VERSION 5.8 ;
BUSBITCHARS "[]" ;
DIVIDERCHAR "/" ;
UNITS
    DATABASE MICRONS 1000 ;
END UNITS

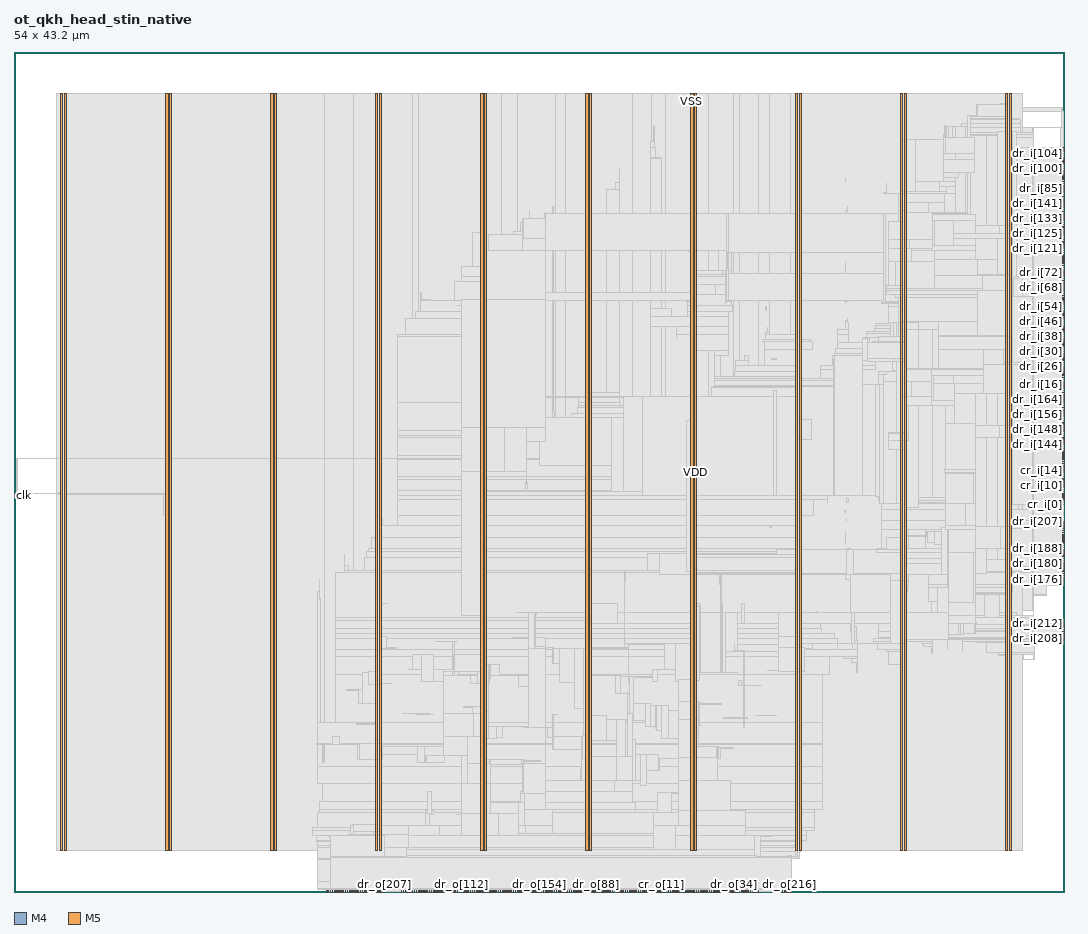
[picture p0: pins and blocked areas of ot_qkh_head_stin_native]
MACRO ot_qkh_head_stin_native
  FOREIGN ot_qkh_head_stin_native 0 0 ;
  CLASS BLOCK ;
  SIZE 54 BY 43.2 ;
  PIN clk
    DIRECTION INPUT ;
    USE SIGNAL ;
    PORT
      LAYER M4 ;
        RECT  0 20.4 0.084 20.424 ;
    END
  END clk
  PIN cr_i[0]
    DIRECTION INPUT ;
    USE SIGNAL ;
    PORT
      LAYER M4 ;
        RECT  53.916 19.92 54 19.944 ;
    END
  END cr_i[0]
  PIN cr_i[10]
    DIRECTION INPUT ;
    USE SIGNAL ;
    PORT
      LAYER M4 ;
        RECT  53.916 20.88 54 20.904 ;
    END
  END cr_i[10]
  PIN cr_i[11]
    DIRECTION INPUT ;
    USE SIGNAL ;
    PORT
      LAYER M4 ;
        RECT  53.916 20.976 54 21 ;
    END
  END cr_i[11]
  PIN cr_i[12]
    DIRECTION INPUT ;
    USE SIGNAL ;
    PORT
      LAYER M4 ;
        RECT  53.916 21.072 54 21.096 ;
    END
  END cr_i[12]
  PIN cr_i[13]
    DIRECTION INPUT ;
    USE SIGNAL ;
    PORT
      LAYER M4 ;
        RECT  53.916 21.168 54 21.192 ;
    END
  END cr_i[13]
  PIN cr_i[14]
    DIRECTION INPUT ;
    USE SIGNAL ;
    PORT
      LAYER M4 ;
        RECT  53.916 21.264 54 21.288 ;
    END
  END cr_i[14]
  PIN cr_i[15]
    DIRECTION INPUT ;
    USE SIGNAL ;
    PORT
      LAYER M4 ;
        RECT  53.916 21.36 54 21.384 ;
    END
  END cr_i[15]
  PIN cr_i[1]
    DIRECTION INPUT ;
    USE SIGNAL ;
    PORT
      LAYER M4 ;
        RECT  53.916 20.016 54 20.04 ;
    END
  END cr_i[1]
  PIN cr_i[2]
    DIRECTION INPUT ;
    USE SIGNAL ;
    PORT
      LAYER M4 ;
        RECT  53.916 20.112 54 20.136 ;
    END
  END cr_i[2]
  PIN cr_i[3]
    DIRECTION INPUT ;
    USE SIGNAL ;
    PORT
      LAYER M4 ;
        RECT  53.916 20.208 54 20.232 ;
    END
  END cr_i[3]
  PIN cr_i[4]
    DIRECTION INPUT ;
    USE SIGNAL ;
    PORT
      LAYER M4 ;
        RECT  53.916 20.304 54 20.328 ;
    END
  END cr_i[4]
  PIN cr_i[5]
    DIRECTION INPUT ;
    USE SIGNAL ;
    PORT
      LAYER M4 ;
        RECT  53.916 20.4 54 20.424 ;
    END
  END cr_i[5]
  PIN cr_i[6]
    DIRECTION INPUT ;
    USE SIGNAL ;
    PORT
      LAYER M4 ;
        RECT  53.916 20.496 54 20.52 ;
    END
  END cr_i[6]
  PIN cr_i[7]
    DIRECTION INPUT ;
    USE SIGNAL ;
    PORT
      LAYER M4 ;
        RECT  53.916 20.592 54 20.616 ;
    END
  END cr_i[7]
  PIN cr_i[8]
    DIRECTION INPUT ;
    USE SIGNAL ;
    PORT
      LAYER M4 ;
        RECT  53.916 20.688 54 20.712 ;
    END
  END cr_i[8]
  PIN cr_i[9]
    DIRECTION INPUT ;
    USE SIGNAL ;
    PORT
      LAYER M4 ;
        RECT  53.916 20.784 54 20.808 ;
    END
  END cr_i[9]
  PIN cr_o[0]
    DIRECTION OUTPUT ;
    USE SIGNAL ;
    PORT
      LAYER M5 ;
        RECT  32.208 0 32.232 0.084 ;
    END
  END cr_o[0]
  PIN cr_o[10]
    DIRECTION OUTPUT ;
    USE SIGNAL ;
    PORT
      LAYER M5 ;
        RECT  33.168 0 33.192 0.084 ;
    END
  END cr_o[10]
  PIN cr_o[11]
    DIRECTION OUTPUT ;
    USE SIGNAL ;
    PORT
      LAYER M5 ;
        RECT  33.264 0 33.288 0.084 ;
    END
  END cr_o[11]
  PIN cr_o[12]
    DIRECTION OUTPUT ;
    USE SIGNAL ;
    PORT
      LAYER M5 ;
        RECT  33.36 0 33.384 0.084 ;
    END
  END cr_o[12]
  PIN cr_o[13]
    DIRECTION OUTPUT ;
    USE SIGNAL ;
    PORT
      LAYER M5 ;
        RECT  33.456 0 33.48 0.084 ;
    END
  END cr_o[13]
  PIN cr_o[14]
    DIRECTION OUTPUT ;
    USE SIGNAL ;
    PORT
      LAYER M5 ;
        RECT  33.552 0 33.576 0.084 ;
    END
  END cr_o[14]
  PIN cr_o[15]
    DIRECTION OUTPUT ;
    USE SIGNAL ;
    PORT
      LAYER M5 ;
        RECT  33.648 0 33.672 0.084 ;
    END
  END cr_o[15]
  PIN cr_o[1]
    DIRECTION OUTPUT ;
    USE SIGNAL ;
    PORT
      LAYER M5 ;
        RECT  32.304 0 32.328 0.084 ;
    END
  END cr_o[1]
  PIN cr_o[2]
    DIRECTION OUTPUT ;
    USE SIGNAL ;
    PORT
      LAYER M5 ;
        RECT  32.4 0 32.424 0.084 ;
    END
  END cr_o[2]
  PIN cr_o[3]
    DIRECTION OUTPUT ;
    USE SIGNAL ;
    PORT
      LAYER M5 ;
        RECT  32.496 0 32.52 0.084 ;
    END
  END cr_o[3]
  PIN cr_o[4]
    DIRECTION OUTPUT ;
    USE SIGNAL ;
    PORT
      LAYER M5 ;
        RECT  32.592 0 32.616 0.084 ;
    END
  END cr_o[4]
  PIN cr_o[5]
    DIRECTION OUTPUT ;
    USE SIGNAL ;
    PORT
      LAYER M5 ;
        RECT  32.688 0 32.712 0.084 ;
    END
  END cr_o[5]
  PIN cr_o[6]
    DIRECTION OUTPUT ;
    USE SIGNAL ;
    PORT
      LAYER M5 ;
        RECT  32.784 0 32.808 0.084 ;
    END
  END cr_o[6]
  PIN cr_o[7]
    DIRECTION OUTPUT ;
    USE SIGNAL ;
    PORT
      LAYER M5 ;
        RECT  32.88 0 32.904 0.084 ;
    END
  END cr_o[7]
  PIN cr_o[8]
    DIRECTION OUTPUT ;
    USE SIGNAL ;
    PORT
      LAYER M5 ;
        RECT  32.976 0 33 0.084 ;
    END
  END cr_o[8]
  PIN cr_o[9]
    DIRECTION OUTPUT ;
    USE SIGNAL ;
    PORT
      LAYER M5 ;
        RECT  33.072 0 33.096 0.084 ;
    END
  END cr_o[9]
  PIN dr_i[0]
    DIRECTION INPUT ;
    USE SIGNAL ;
    PORT
      LAYER M4 ;
        RECT  53.916 21.456 54 21.48 ;
    END
  END dr_i[0]
  PIN dr_i[100]
    DIRECTION INPUT ;
    USE SIGNAL ;
    PORT
      LAYER M4 ;
        RECT  53.916 37.2 54 37.224 ;
    END
  END dr_i[100]
  PIN dr_i[101]
    DIRECTION INPUT ;
    USE SIGNAL ;
    PORT
      LAYER M4 ;
        RECT  53.916 37.296 54 37.32 ;
    END
  END dr_i[101]
  PIN dr_i[102]
    DIRECTION INPUT ;
    USE SIGNAL ;
    PORT
      LAYER M4 ;
        RECT  53.916 37.392 54 37.416 ;
    END
  END dr_i[102]
  PIN dr_i[103]
    DIRECTION INPUT ;
    USE SIGNAL ;
    PORT
      LAYER M4 ;
        RECT  53.916 37.488 54 37.512 ;
    END
  END dr_i[103]
  PIN dr_i[104]
    DIRECTION INPUT ;
    USE SIGNAL ;
    PORT
      LAYER M4 ;
        RECT  53.916 37.584 54 37.608 ;
    END
  END dr_i[104]
  PIN dr_i[105]
    DIRECTION INPUT ;
    USE SIGNAL ;
    PORT
      LAYER M4 ;
        RECT  53.916 37.68 54 37.704 ;
    END
  END dr_i[105]
  PIN dr_i[106]
    DIRECTION INPUT ;
    USE SIGNAL ;
    PORT
      LAYER M4 ;
        RECT  53.916 37.776 54 37.8 ;
    END
  END dr_i[106]
  PIN dr_i[107]
    DIRECTION INPUT ;
    USE SIGNAL ;
    PORT
      LAYER M4 ;
        RECT  53.916 37.872 54 37.896 ;
    END
  END dr_i[107]
  PIN dr_i[108]
    DIRECTION INPUT ;
    USE SIGNAL ;
    PORT
      LAYER M4 ;
        RECT  53.916 37.968 54 37.992 ;
    END
  END dr_i[108]
  PIN dr_i[109]
    DIRECTION INPUT ;
    USE SIGNAL ;
    PORT
      LAYER M4 ;
        RECT  53.916 38.064 54 38.088 ;
    END
  END dr_i[109]
  PIN dr_i[10]
    DIRECTION INPUT ;
    USE SIGNAL ;
    PORT
      LAYER M4 ;
        RECT  53.916 22.416 54 22.44 ;
    END
  END dr_i[10]
  PIN dr_i[110]
    DIRECTION INPUT ;
    USE SIGNAL ;
    PORT
      LAYER M4 ;
        RECT  53.916 38.16 54 38.184 ;
    END
  END dr_i[110]
  PIN dr_i[111]
    DIRECTION INPUT ;
    USE SIGNAL ;
    PORT
      LAYER M4 ;
        RECT  53.916 38.256 54 38.28 ;
    END
  END dr_i[111]
  PIN dr_i[112]
    DIRECTION INPUT ;
    USE SIGNAL ;
    PORT
      LAYER M4 ;
        RECT  53.916 32.208 54 32.232 ;
    END
  END dr_i[112]
  PIN dr_i[113]
    DIRECTION INPUT ;
    USE SIGNAL ;
    PORT
      LAYER M4 ;
        RECT  53.916 32.304 54 32.328 ;
    END
  END dr_i[113]
  PIN dr_i[114]
    DIRECTION INPUT ;
    USE SIGNAL ;
    PORT
      LAYER M4 ;
        RECT  53.916 32.4 54 32.424 ;
    END
  END dr_i[114]
  PIN dr_i[115]
    DIRECTION INPUT ;
    USE SIGNAL ;
    PORT
      LAYER M4 ;
        RECT  53.916 32.496 54 32.52 ;
    END
  END dr_i[115]
  PIN dr_i[116]
    DIRECTION INPUT ;
    USE SIGNAL ;
    PORT
      LAYER M4 ;
        RECT  53.916 32.592 54 32.616 ;
    END
  END dr_i[116]
  PIN dr_i[117]
    DIRECTION INPUT ;
    USE SIGNAL ;
    PORT
      LAYER M4 ;
        RECT  53.916 32.688 54 32.712 ;
    END
  END dr_i[117]
  PIN dr_i[118]
    DIRECTION INPUT ;
    USE SIGNAL ;
    PORT
      LAYER M4 ;
        RECT  53.916 32.784 54 32.808 ;
    END
  END dr_i[118]
  PIN dr_i[119]
    DIRECTION INPUT ;
    USE SIGNAL ;
    PORT
      LAYER M4 ;
        RECT  53.916 32.88 54 32.904 ;
    END
  END dr_i[119]
  PIN dr_i[11]
    DIRECTION INPUT ;
    USE SIGNAL ;
    PORT
      LAYER M4 ;
        RECT  53.916 22.512 54 22.536 ;
    END
  END dr_i[11]
  PIN dr_i[120]
    DIRECTION INPUT ;
    USE SIGNAL ;
    PORT
      LAYER M4 ;
        RECT  53.916 32.976 54 33 ;
    END
  END dr_i[120]
  PIN dr_i[121]
    DIRECTION INPUT ;
    USE SIGNAL ;
    PORT
      LAYER M4 ;
        RECT  53.916 33.072 54 33.096 ;
    END
  END dr_i[121]
  PIN dr_i[122]
    DIRECTION INPUT ;
    USE SIGNAL ;
    PORT
      LAYER M4 ;
        RECT  53.916 33.168 54 33.192 ;
    END
  END dr_i[122]
  PIN dr_i[123]
    DIRECTION INPUT ;
    USE SIGNAL ;
    PORT
      LAYER M4 ;
        RECT  53.916 33.264 54 33.288 ;
    END
  END dr_i[123]
  PIN dr_i[124]
    DIRECTION INPUT ;
    USE SIGNAL ;
    PORT
      LAYER M4 ;
        RECT  53.916 33.36 54 33.384 ;
    END
  END dr_i[124]
  PIN dr_i[125]
    DIRECTION INPUT ;
    USE SIGNAL ;
    PORT
      LAYER M4 ;
        RECT  53.916 33.456 54 33.48 ;
    END
  END dr_i[125]
  PIN dr_i[126]
    DIRECTION INPUT ;
    USE SIGNAL ;
    PORT
      LAYER M4 ;
        RECT  53.916 33.552 54 33.576 ;
    END
  END dr_i[126]
  PIN dr_i[127]
    DIRECTION INPUT ;
    USE SIGNAL ;
    PORT
      LAYER M4 ;
        RECT  53.916 33.648 54 33.672 ;
    END
  END dr_i[127]
  PIN dr_i[128]
    DIRECTION INPUT ;
    USE SIGNAL ;
    PORT
      LAYER M4 ;
        RECT  53.916 33.744 54 33.768 ;
    END
  END dr_i[128]
  PIN dr_i[129]
    DIRECTION INPUT ;
    USE SIGNAL ;
    PORT
      LAYER M4 ;
        RECT  53.916 33.84 54 33.864 ;
    END
  END dr_i[129]
  PIN dr_i[12]
    DIRECTION INPUT ;
    USE SIGNAL ;
    PORT
      LAYER M4 ;
        RECT  53.916 22.608 54 22.632 ;
    END
  END dr_i[12]
  PIN dr_i[130]
    DIRECTION INPUT ;
    USE SIGNAL ;
    PORT
      LAYER M4 ;
        RECT  53.916 33.936 54 33.96 ;
    END
  END dr_i[130]
  PIN dr_i[131]
    DIRECTION INPUT ;
    USE SIGNAL ;
    PORT
      LAYER M4 ;
        RECT  53.916 34.032 54 34.056 ;
    END
  END dr_i[131]
  PIN dr_i[132]
    DIRECTION INPUT ;
    USE SIGNAL ;
    PORT
      LAYER M4 ;
        RECT  53.916 34.128 54 34.152 ;
    END
  END dr_i[132]
  PIN dr_i[133]
    DIRECTION INPUT ;
    USE SIGNAL ;
    PORT
      LAYER M4 ;
        RECT  53.916 34.224 54 34.248 ;
    END
  END dr_i[133]
  PIN dr_i[134]
    DIRECTION INPUT ;
    USE SIGNAL ;
    PORT
      LAYER M4 ;
        RECT  53.916 34.32 54 34.344 ;
    END
  END dr_i[134]
  PIN dr_i[135]
    DIRECTION INPUT ;
    USE SIGNAL ;
    PORT
      LAYER M4 ;
        RECT  53.916 34.416 54 34.44 ;
    END
  END dr_i[135]
  PIN dr_i[136]
    DIRECTION INPUT ;
    USE SIGNAL ;
    PORT
      LAYER M4 ;
        RECT  53.916 34.512 54 34.536 ;
    END
  END dr_i[136]
  PIN dr_i[137]
    DIRECTION INPUT ;
    USE SIGNAL ;
    PORT
      LAYER M4 ;
        RECT  53.916 34.608 54 34.632 ;
    END
  END dr_i[137]
  PIN dr_i[138]
    DIRECTION INPUT ;
    USE SIGNAL ;
    PORT
      LAYER M4 ;
        RECT  53.916 34.704 54 34.728 ;
    END
  END dr_i[138]
  PIN dr_i[139]
    DIRECTION INPUT ;
    USE SIGNAL ;
    PORT
      LAYER M4 ;
        RECT  53.916 34.8 54 34.824 ;
    END
  END dr_i[139]
  PIN dr_i[13]
    DIRECTION INPUT ;
    USE SIGNAL ;
    PORT
      LAYER M4 ;
        RECT  53.916 22.704 54 22.728 ;
    END
  END dr_i[13]
  PIN dr_i[140]
    DIRECTION INPUT ;
    USE SIGNAL ;
    PORT
      LAYER M4 ;
        RECT  53.916 34.896 54 34.92 ;
    END
  END dr_i[140]
  PIN dr_i[141]
    DIRECTION INPUT ;
    USE SIGNAL ;
    PORT
      LAYER M4 ;
        RECT  53.916 34.992 54 35.016 ;
    END
  END dr_i[141]
  PIN dr_i[142]
    DIRECTION INPUT ;
    USE SIGNAL ;
    PORT
      LAYER M4 ;
        RECT  53.916 35.088 54 35.112 ;
    END
  END dr_i[142]
  PIN dr_i[143]
    DIRECTION INPUT ;
    USE SIGNAL ;
    PORT
      LAYER M4 ;
        RECT  53.916 35.184 54 35.208 ;
    END
  END dr_i[143]
  PIN dr_i[144]
    DIRECTION INPUT ;
    USE SIGNAL ;
    PORT
      LAYER M4 ;
        RECT  53.916 22.992 54 23.016 ;
    END
  END dr_i[144]
  PIN dr_i[145]
    DIRECTION INPUT ;
    USE SIGNAL ;
    PORT
      LAYER M4 ;
        RECT  53.916 23.088 54 23.112 ;
    END
  END dr_i[145]
  PIN dr_i[146]
    DIRECTION INPUT ;
    USE SIGNAL ;
    PORT
      LAYER M4 ;
        RECT  53.916 23.184 54 23.208 ;
    END
  END dr_i[146]
  PIN dr_i[147]
    DIRECTION INPUT ;
    USE SIGNAL ;
    PORT
      LAYER M4 ;
        RECT  53.916 23.28 54 23.304 ;
    END
  END dr_i[147]
  PIN dr_i[148]
    DIRECTION INPUT ;
    USE SIGNAL ;
    PORT
      LAYER M4 ;
        RECT  53.916 23.376 54 23.4 ;
    END
  END dr_i[148]
  PIN dr_i[149]
    DIRECTION INPUT ;
    USE SIGNAL ;
    PORT
      LAYER M4 ;
        RECT  53.916 23.472 54 23.496 ;
    END
  END dr_i[149]
  PIN dr_i[14]
    DIRECTION INPUT ;
    USE SIGNAL ;
    PORT
      LAYER M4 ;
        RECT  53.916 22.8 54 22.824 ;
    END
  END dr_i[14]
  PIN dr_i[150]
    DIRECTION INPUT ;
    USE SIGNAL ;
    PORT
      LAYER M4 ;
        RECT  53.916 23.568 54 23.592 ;
    END
  END dr_i[150]
  PIN dr_i[151]
    DIRECTION INPUT ;
    USE SIGNAL ;
    PORT
      LAYER M4 ;
        RECT  53.916 23.664 54 23.688 ;
    END
  END dr_i[151]
  PIN dr_i[152]
    DIRECTION INPUT ;
    USE SIGNAL ;
    PORT
      LAYER M4 ;
        RECT  53.916 23.76 54 23.784 ;
    END
  END dr_i[152]
  PIN dr_i[153]
    DIRECTION INPUT ;
    USE SIGNAL ;
    PORT
      LAYER M4 ;
        RECT  53.916 23.856 54 23.88 ;
    END
  END dr_i[153]
  PIN dr_i[154]
    DIRECTION INPUT ;
    USE SIGNAL ;
    PORT
      LAYER M4 ;
        RECT  53.916 23.952 54 23.976 ;
    END
  END dr_i[154]
  PIN dr_i[155]
    DIRECTION INPUT ;
    USE SIGNAL ;
    PORT
      LAYER M4 ;
        RECT  53.916 24.048 54 24.072 ;
    END
  END dr_i[155]
  PIN dr_i[156]
    DIRECTION INPUT ;
    USE SIGNAL ;
    PORT
      LAYER M4 ;
        RECT  53.916 24.144 54 24.168 ;
    END
  END dr_i[156]
  PIN dr_i[157]
    DIRECTION INPUT ;
    USE SIGNAL ;
    PORT
      LAYER M4 ;
        RECT  53.916 24.24 54 24.264 ;
    END
  END dr_i[157]
  PIN dr_i[158]
    DIRECTION INPUT ;
    USE SIGNAL ;
    PORT
      LAYER M4 ;
        RECT  53.916 24.336 54 24.36 ;
    END
  END dr_i[158]
  PIN dr_i[159]
    DIRECTION INPUT ;
    USE SIGNAL ;
    PORT
      LAYER M4 ;
        RECT  53.916 24.432 54 24.456 ;
    END
  END dr_i[159]
  PIN dr_i[15]
    DIRECTION INPUT ;
    USE SIGNAL ;
    PORT
      LAYER M4 ;
        RECT  53.916 22.896 54 22.92 ;
    END
  END dr_i[15]
  PIN dr_i[160]
    DIRECTION INPUT ;
    USE SIGNAL ;
    PORT
      LAYER M4 ;
        RECT  53.916 24.528 54 24.552 ;
    END
  END dr_i[160]
  PIN dr_i[161]
    DIRECTION INPUT ;
    USE SIGNAL ;
    PORT
      LAYER M4 ;
        RECT  53.916 24.624 54 24.648 ;
    END
  END dr_i[161]
  PIN dr_i[162]
    DIRECTION INPUT ;
    USE SIGNAL ;
    PORT
      LAYER M4 ;
        RECT  53.916 24.72 54 24.744 ;
    END
  END dr_i[162]
  PIN dr_i[163]
    DIRECTION INPUT ;
    USE SIGNAL ;
    PORT
      LAYER M4 ;
        RECT  53.916 24.816 54 24.84 ;
    END
  END dr_i[163]
  PIN dr_i[164]
    DIRECTION INPUT ;
    USE SIGNAL ;
    PORT
      LAYER M4 ;
        RECT  53.916 24.912 54 24.936 ;
    END
  END dr_i[164]
  PIN dr_i[165]
    DIRECTION INPUT ;
    USE SIGNAL ;
    PORT
      LAYER M4 ;
        RECT  53.916 25.008 54 25.032 ;
    END
  END dr_i[165]
  PIN dr_i[166]
    DIRECTION INPUT ;
    USE SIGNAL ;
    PORT
      LAYER M4 ;
        RECT  53.916 25.104 54 25.128 ;
    END
  END dr_i[166]
  PIN dr_i[167]
    DIRECTION INPUT ;
    USE SIGNAL ;
    PORT
      LAYER M4 ;
        RECT  53.916 25.2 54 25.224 ;
    END
  END dr_i[167]
  PIN dr_i[168]
    DIRECTION INPUT ;
    USE SIGNAL ;
    PORT
      LAYER M4 ;
        RECT  53.916 25.296 54 25.32 ;
    END
  END dr_i[168]
  PIN dr_i[169]
    DIRECTION INPUT ;
    USE SIGNAL ;
    PORT
      LAYER M4 ;
        RECT  53.916 25.392 54 25.416 ;
    END
  END dr_i[169]
  PIN dr_i[16]
    DIRECTION INPUT ;
    USE SIGNAL ;
    PORT
      LAYER M4 ;
        RECT  53.916 26.064 54 26.088 ;
    END
  END dr_i[16]
  PIN dr_i[170]
    DIRECTION INPUT ;
    USE SIGNAL ;
    PORT
      LAYER M4 ;
        RECT  53.916 25.488 54 25.512 ;
    END
  END dr_i[170]
  PIN dr_i[171]
    DIRECTION INPUT ;
    USE SIGNAL ;
    PORT
      LAYER M4 ;
        RECT  53.916 25.584 54 25.608 ;
    END
  END dr_i[171]
  PIN dr_i[172]
    DIRECTION INPUT ;
    USE SIGNAL ;
    PORT
      LAYER M4 ;
        RECT  53.916 25.68 54 25.704 ;
    END
  END dr_i[172]
  PIN dr_i[173]
    DIRECTION INPUT ;
    USE SIGNAL ;
    PORT
      LAYER M4 ;
        RECT  53.916 25.776 54 25.8 ;
    END
  END dr_i[173]
  PIN dr_i[174]
    DIRECTION INPUT ;
    USE SIGNAL ;
    PORT
      LAYER M4 ;
        RECT  53.916 25.872 54 25.896 ;
    END
  END dr_i[174]
  PIN dr_i[175]
    DIRECTION INPUT ;
    USE SIGNAL ;
    PORT
      LAYER M4 ;
        RECT  53.916 25.968 54 25.992 ;
    END
  END dr_i[175]
  PIN dr_i[176]
    DIRECTION INPUT ;
    USE SIGNAL ;
    PORT
      LAYER M4 ;
        RECT  53.916 16.08 54 16.104 ;
    END
  END dr_i[176]
  PIN dr_i[177]
    DIRECTION INPUT ;
    USE SIGNAL ;
    PORT
      LAYER M4 ;
        RECT  53.916 16.176 54 16.2 ;
    END
  END dr_i[177]
  PIN dr_i[178]
    DIRECTION INPUT ;
    USE SIGNAL ;
    PORT
      LAYER M4 ;
        RECT  53.916 16.272 54 16.296 ;
    END
  END dr_i[178]
  PIN dr_i[179]
    DIRECTION INPUT ;
    USE SIGNAL ;
    PORT
      LAYER M4 ;
        RECT  53.916 16.368 54 16.392 ;
    END
  END dr_i[179]
  PIN dr_i[17]
    DIRECTION INPUT ;
    USE SIGNAL ;
    PORT
      LAYER M4 ;
        RECT  53.916 26.16 54 26.184 ;
    END
  END dr_i[17]
  PIN dr_i[180]
    DIRECTION INPUT ;
    USE SIGNAL ;
    PORT
      LAYER M4 ;
        RECT  53.916 16.464 54 16.488 ;
    END
  END dr_i[180]
  PIN dr_i[181]
    DIRECTION INPUT ;
    USE SIGNAL ;
    PORT
      LAYER M4 ;
        RECT  53.916 16.56 54 16.584 ;
    END
  END dr_i[181]
  PIN dr_i[182]
    DIRECTION INPUT ;
    USE SIGNAL ;
    PORT
      LAYER M4 ;
        RECT  53.916 16.656 54 16.68 ;
    END
  END dr_i[182]
  PIN dr_i[183]
    DIRECTION INPUT ;
    USE SIGNAL ;
    PORT
      LAYER M4 ;
        RECT  53.916 16.752 54 16.776 ;
    END
  END dr_i[183]
  PIN dr_i[184]
    DIRECTION INPUT ;
    USE SIGNAL ;
    PORT
      LAYER M4 ;
        RECT  53.916 16.848 54 16.872 ;
    END
  END dr_i[184]
  PIN dr_i[185]
    DIRECTION INPUT ;
    USE SIGNAL ;
    PORT
      LAYER M4 ;
        RECT  53.916 16.944 54 16.968 ;
    END
  END dr_i[185]
  PIN dr_i[186]
    DIRECTION INPUT ;
    USE SIGNAL ;
    PORT
      LAYER M4 ;
        RECT  53.916 17.04 54 17.064 ;
    END
  END dr_i[186]
  PIN dr_i[187]
    DIRECTION INPUT ;
    USE SIGNAL ;
    PORT
      LAYER M4 ;
        RECT  53.916 17.136 54 17.16 ;
    END
  END dr_i[187]
  PIN dr_i[188]
    DIRECTION INPUT ;
    USE SIGNAL ;
    PORT
      LAYER M4 ;
        RECT  53.916 17.232 54 17.256 ;
    END
  END dr_i[188]
  PIN dr_i[189]
    DIRECTION INPUT ;
    USE SIGNAL ;
    PORT
      LAYER M4 ;
        RECT  53.916 17.328 54 17.352 ;
    END
  END dr_i[189]
  PIN dr_i[18]
    DIRECTION INPUT ;
    USE SIGNAL ;
    PORT
      LAYER M4 ;
        RECT  53.916 26.256 54 26.28 ;
    END
  END dr_i[18]
  PIN dr_i[190]
    DIRECTION INPUT ;
    USE SIGNAL ;
    PORT
      LAYER M4 ;
        RECT  53.916 17.424 54 17.448 ;
    END
  END dr_i[190]
  PIN dr_i[191]
    DIRECTION INPUT ;
    USE SIGNAL ;
    PORT
      LAYER M4 ;
        RECT  53.916 17.52 54 17.544 ;
    END
  END dr_i[191]
  PIN dr_i[192]
    DIRECTION INPUT ;
    USE SIGNAL ;
    PORT
      LAYER M4 ;
        RECT  53.916 17.616 54 17.64 ;
    END
  END dr_i[192]
  PIN dr_i[193]
    DIRECTION INPUT ;
    USE SIGNAL ;
    PORT
      LAYER M4 ;
        RECT  53.916 17.712 54 17.736 ;
    END
  END dr_i[193]
  PIN dr_i[194]
    DIRECTION INPUT ;
    USE SIGNAL ;
    PORT
      LAYER M4 ;
        RECT  53.916 17.808 54 17.832 ;
    END
  END dr_i[194]
  PIN dr_i[195]
    DIRECTION INPUT ;
    USE SIGNAL ;
    PORT
      LAYER M4 ;
        RECT  53.916 17.904 54 17.928 ;
    END
  END dr_i[195]
  PIN dr_i[196]
    DIRECTION INPUT ;
    USE SIGNAL ;
    PORT
      LAYER M4 ;
        RECT  53.916 18 54 18.024 ;
    END
  END dr_i[196]
  PIN dr_i[197]
    DIRECTION INPUT ;
    USE SIGNAL ;
    PORT
      LAYER M4 ;
        RECT  53.916 18.096 54 18.12 ;
    END
  END dr_i[197]
  PIN dr_i[198]
    DIRECTION INPUT ;
    USE SIGNAL ;
    PORT
      LAYER M4 ;
        RECT  53.916 18.192 54 18.216 ;
    END
  END dr_i[198]
  PIN dr_i[199]
    DIRECTION INPUT ;
    USE SIGNAL ;
    PORT
      LAYER M4 ;
        RECT  53.916 18.288 54 18.312 ;
    END
  END dr_i[199]
  PIN dr_i[19]
    DIRECTION INPUT ;
    USE SIGNAL ;
    PORT
      LAYER M4 ;
        RECT  53.916 26.352 54 26.376 ;
    END
  END dr_i[19]
  PIN dr_i[1]
    DIRECTION INPUT ;
    USE SIGNAL ;
    PORT
      LAYER M4 ;
        RECT  53.916 21.552 54 21.576 ;
    END
  END dr_i[1]
  PIN dr_i[200]
    DIRECTION INPUT ;
    USE SIGNAL ;
    PORT
      LAYER M4 ;
        RECT  53.916 18.384 54 18.408 ;
    END
  END dr_i[200]
  PIN dr_i[201]
    DIRECTION INPUT ;
    USE SIGNAL ;
    PORT
      LAYER M4 ;
        RECT  53.916 18.48 54 18.504 ;
    END
  END dr_i[201]
  PIN dr_i[202]
    DIRECTION INPUT ;
    USE SIGNAL ;
    PORT
      LAYER M4 ;
        RECT  53.916 18.576 54 18.6 ;
    END
  END dr_i[202]
  PIN dr_i[203]
    DIRECTION INPUT ;
    USE SIGNAL ;
    PORT
      LAYER M4 ;
        RECT  53.916 18.672 54 18.696 ;
    END
  END dr_i[203]
  PIN dr_i[204]
    DIRECTION INPUT ;
    USE SIGNAL ;
    PORT
      LAYER M4 ;
        RECT  53.916 18.768 54 18.792 ;
    END
  END dr_i[204]
  PIN dr_i[205]
    DIRECTION INPUT ;
    USE SIGNAL ;
    PORT
      LAYER M4 ;
        RECT  53.916 18.864 54 18.888 ;
    END
  END dr_i[205]
  PIN dr_i[206]
    DIRECTION INPUT ;
    USE SIGNAL ;
    PORT
      LAYER M4 ;
        RECT  53.916 18.96 54 18.984 ;
    END
  END dr_i[206]
  PIN dr_i[207]
    DIRECTION INPUT ;
    USE SIGNAL ;
    PORT
      LAYER M4 ;
        RECT  53.916 19.056 54 19.08 ;
    END
  END dr_i[207]
  PIN dr_i[208]
    DIRECTION INPUT ;
    USE SIGNAL ;
    PORT
      LAYER M4 ;
        RECT  53.916 13.008 54 13.032 ;
    END
  END dr_i[208]
  PIN dr_i[209]
    DIRECTION INPUT ;
    USE SIGNAL ;
    PORT
      LAYER M4 ;
        RECT  53.916 13.104 54 13.128 ;
    END
  END dr_i[209]
  PIN dr_i[20]
    DIRECTION INPUT ;
    USE SIGNAL ;
    PORT
      LAYER M4 ;
        RECT  53.916 26.448 54 26.472 ;
    END
  END dr_i[20]
  PIN dr_i[210]
    DIRECTION INPUT ;
    USE SIGNAL ;
    PORT
      LAYER M4 ;
        RECT  53.916 13.2 54 13.224 ;
    END
  END dr_i[210]
  PIN dr_i[211]
    DIRECTION INPUT ;
    USE SIGNAL ;
    PORT
      LAYER M4 ;
        RECT  53.916 13.296 54 13.32 ;
    END
  END dr_i[211]
  PIN dr_i[212]
    DIRECTION INPUT ;
    USE SIGNAL ;
    PORT
      LAYER M4 ;
        RECT  53.916 13.392 54 13.416 ;
    END
  END dr_i[212]
  PIN dr_i[213]
    DIRECTION INPUT ;
    USE SIGNAL ;
    PORT
      LAYER M4 ;
        RECT  53.916 13.488 54 13.512 ;
    END
  END dr_i[213]
  PIN dr_i[214]
    DIRECTION INPUT ;
    USE SIGNAL ;
    PORT
      LAYER M4 ;
        RECT  53.916 13.584 54 13.608 ;
    END
  END dr_i[214]
  PIN dr_i[215]
    DIRECTION INPUT ;
    USE SIGNAL ;
    PORT
      LAYER M4 ;
        RECT  53.916 13.68 54 13.704 ;
    END
  END dr_i[215]
  PIN dr_i[216]
    DIRECTION INPUT ;
    USE SIGNAL ;
    PORT
      LAYER M4 ;
        RECT  53.916 13.776 54 13.8 ;
    END
  END dr_i[216]
  PIN dr_i[21]
    DIRECTION INPUT ;
    USE SIGNAL ;
    PORT
      LAYER M4 ;
        RECT  53.916 26.544 54 26.568 ;
    END
  END dr_i[21]
  PIN dr_i[22]
    DIRECTION INPUT ;
    USE SIGNAL ;
    PORT
      LAYER M4 ;
        RECT  53.916 26.64 54 26.664 ;
    END
  END dr_i[22]
  PIN dr_i[23]
    DIRECTION INPUT ;
    USE SIGNAL ;
    PORT
      LAYER M4 ;
        RECT  53.916 26.736 54 26.76 ;
    END
  END dr_i[23]
  PIN dr_i[24]
    DIRECTION INPUT ;
    USE SIGNAL ;
    PORT
      LAYER M4 ;
        RECT  53.916 26.832 54 26.856 ;
    END
  END dr_i[24]
  PIN dr_i[25]
    DIRECTION INPUT ;
    USE SIGNAL ;
    PORT
      LAYER M4 ;
        RECT  53.916 26.928 54 26.952 ;
    END
  END dr_i[25]
  PIN dr_i[26]
    DIRECTION INPUT ;
    USE SIGNAL ;
    PORT
      LAYER M4 ;
        RECT  53.916 27.024 54 27.048 ;
    END
  END dr_i[26]
  PIN dr_i[27]
    DIRECTION INPUT ;
    USE SIGNAL ;
    PORT
      LAYER M4 ;
        RECT  53.916 27.12 54 27.144 ;
    END
  END dr_i[27]
  PIN dr_i[28]
    DIRECTION INPUT ;
    USE SIGNAL ;
    PORT
      LAYER M4 ;
        RECT  53.916 27.216 54 27.24 ;
    END
  END dr_i[28]
  PIN dr_i[29]
    DIRECTION INPUT ;
    USE SIGNAL ;
    PORT
      LAYER M4 ;
        RECT  53.916 27.312 54 27.336 ;
    END
  END dr_i[29]
  PIN dr_i[2]
    DIRECTION INPUT ;
    USE SIGNAL ;
    PORT
      LAYER M4 ;
        RECT  53.916 21.648 54 21.672 ;
    END
  END dr_i[2]
  PIN dr_i[30]
    DIRECTION INPUT ;
    USE SIGNAL ;
    PORT
      LAYER M4 ;
        RECT  53.916 27.408 54 27.432 ;
    END
  END dr_i[30]
  PIN dr_i[31]
    DIRECTION INPUT ;
    USE SIGNAL ;
    PORT
      LAYER M4 ;
        RECT  53.916 27.504 54 27.528 ;
    END
  END dr_i[31]
  PIN dr_i[32]
    DIRECTION INPUT ;
    USE SIGNAL ;
    PORT
      LAYER M4 ;
        RECT  53.916 27.6 54 27.624 ;
    END
  END dr_i[32]
  PIN dr_i[33]
    DIRECTION INPUT ;
    USE SIGNAL ;
    PORT
      LAYER M4 ;
        RECT  53.916 27.696 54 27.72 ;
    END
  END dr_i[33]
  PIN dr_i[34]
    DIRECTION INPUT ;
    USE SIGNAL ;
    PORT
      LAYER M4 ;
        RECT  53.916 27.792 54 27.816 ;
    END
  END dr_i[34]
  PIN dr_i[35]
    DIRECTION INPUT ;
    USE SIGNAL ;
    PORT
      LAYER M4 ;
        RECT  53.916 27.888 54 27.912 ;
    END
  END dr_i[35]
  PIN dr_i[36]
    DIRECTION INPUT ;
    USE SIGNAL ;
    PORT
      LAYER M4 ;
        RECT  53.916 27.984 54 28.008 ;
    END
  END dr_i[36]
  PIN dr_i[37]
    DIRECTION INPUT ;
    USE SIGNAL ;
    PORT
      LAYER M4 ;
        RECT  53.916 28.08 54 28.104 ;
    END
  END dr_i[37]
  PIN dr_i[38]
    DIRECTION INPUT ;
    USE SIGNAL ;
    PORT
      LAYER M4 ;
        RECT  53.916 28.176 54 28.2 ;
    END
  END dr_i[38]
  PIN dr_i[39]
    DIRECTION INPUT ;
    USE SIGNAL ;
    PORT
      LAYER M4 ;
        RECT  53.916 28.272 54 28.296 ;
    END
  END dr_i[39]
  PIN dr_i[3]
    DIRECTION INPUT ;
    USE SIGNAL ;
    PORT
      LAYER M4 ;
        RECT  53.916 21.744 54 21.768 ;
    END
  END dr_i[3]
  PIN dr_i[40]
    DIRECTION INPUT ;
    USE SIGNAL ;
    PORT
      LAYER M4 ;
        RECT  53.916 28.368 54 28.392 ;
    END
  END dr_i[40]
  PIN dr_i[41]
    DIRECTION INPUT ;
    USE SIGNAL ;
    PORT
      LAYER M4 ;
        RECT  53.916 28.464 54 28.488 ;
    END
  END dr_i[41]
  PIN dr_i[42]
    DIRECTION INPUT ;
    USE SIGNAL ;
    PORT
      LAYER M4 ;
        RECT  53.916 28.56 54 28.584 ;
    END
  END dr_i[42]
  PIN dr_i[43]
    DIRECTION INPUT ;
    USE SIGNAL ;
    PORT
      LAYER M4 ;
        RECT  53.916 28.656 54 28.68 ;
    END
  END dr_i[43]
  PIN dr_i[44]
    DIRECTION INPUT ;
    USE SIGNAL ;
    PORT
      LAYER M4 ;
        RECT  53.916 28.752 54 28.776 ;
    END
  END dr_i[44]
  PIN dr_i[45]
    DIRECTION INPUT ;
    USE SIGNAL ;
    PORT
      LAYER M4 ;
        RECT  53.916 28.848 54 28.872 ;
    END
  END dr_i[45]
  PIN dr_i[46]
    DIRECTION INPUT ;
    USE SIGNAL ;
    PORT
      LAYER M4 ;
        RECT  53.916 28.944 54 28.968 ;
    END
  END dr_i[46]
  PIN dr_i[47]
    DIRECTION INPUT ;
    USE SIGNAL ;
    PORT
      LAYER M4 ;
        RECT  53.916 29.04 54 29.064 ;
    END
  END dr_i[47]
  PIN dr_i[48]
    DIRECTION INPUT ;
    USE SIGNAL ;
    PORT
      LAYER M4 ;
        RECT  53.916 29.136 54 29.16 ;
    END
  END dr_i[48]
  PIN dr_i[49]
    DIRECTION INPUT ;
    USE SIGNAL ;
    PORT
      LAYER M4 ;
        RECT  53.916 29.232 54 29.256 ;
    END
  END dr_i[49]
  PIN dr_i[4]
    DIRECTION INPUT ;
    USE SIGNAL ;
    PORT
      LAYER M4 ;
        RECT  53.916 21.84 54 21.864 ;
    END
  END dr_i[4]
  PIN dr_i[50]
    DIRECTION INPUT ;
    USE SIGNAL ;
    PORT
      LAYER M4 ;
        RECT  53.916 29.328 54 29.352 ;
    END
  END dr_i[50]
  PIN dr_i[51]
    DIRECTION INPUT ;
    USE SIGNAL ;
    PORT
      LAYER M4 ;
        RECT  53.916 29.424 54 29.448 ;
    END
  END dr_i[51]
  PIN dr_i[52]
    DIRECTION INPUT ;
    USE SIGNAL ;
    PORT
      LAYER M4 ;
        RECT  53.916 29.52 54 29.544 ;
    END
  END dr_i[52]
  PIN dr_i[53]
    DIRECTION INPUT ;
    USE SIGNAL ;
    PORT
      LAYER M4 ;
        RECT  53.916 29.616 54 29.64 ;
    END
  END dr_i[53]
  PIN dr_i[54]
    DIRECTION INPUT ;
    USE SIGNAL ;
    PORT
      LAYER M4 ;
        RECT  53.916 29.712 54 29.736 ;
    END
  END dr_i[54]
  PIN dr_i[55]
    DIRECTION INPUT ;
    USE SIGNAL ;
    PORT
      LAYER M4 ;
        RECT  53.916 29.808 54 29.832 ;
    END
  END dr_i[55]
  PIN dr_i[56]
    DIRECTION INPUT ;
    USE SIGNAL ;
    PORT
      LAYER M4 ;
        RECT  53.916 29.904 54 29.928 ;
    END
  END dr_i[56]
  PIN dr_i[57]
    DIRECTION INPUT ;
    USE SIGNAL ;
    PORT
      LAYER M4 ;
        RECT  53.916 30 54 30.024 ;
    END
  END dr_i[57]
  PIN dr_i[58]
    DIRECTION INPUT ;
    USE SIGNAL ;
    PORT
      LAYER M4 ;
        RECT  53.916 30.096 54 30.12 ;
    END
  END dr_i[58]
  PIN dr_i[59]
    DIRECTION INPUT ;
    USE SIGNAL ;
    PORT
      LAYER M4 ;
        RECT  53.916 30.192 54 30.216 ;
    END
  END dr_i[59]
  PIN dr_i[5]
    DIRECTION INPUT ;
    USE SIGNAL ;
    PORT
      LAYER M4 ;
        RECT  53.916 21.936 54 21.96 ;
    END
  END dr_i[5]
  PIN dr_i[60]
    DIRECTION INPUT ;
    USE SIGNAL ;
    PORT
      LAYER M4 ;
        RECT  53.916 30.288 54 30.312 ;
    END
  END dr_i[60]
  PIN dr_i[61]
    DIRECTION INPUT ;
    USE SIGNAL ;
    PORT
      LAYER M4 ;
        RECT  53.916 30.384 54 30.408 ;
    END
  END dr_i[61]
  PIN dr_i[62]
    DIRECTION INPUT ;
    USE SIGNAL ;
    PORT
      LAYER M4 ;
        RECT  53.916 30.48 54 30.504 ;
    END
  END dr_i[62]
  PIN dr_i[63]
    DIRECTION INPUT ;
    USE SIGNAL ;
    PORT
      LAYER M4 ;
        RECT  53.916 30.576 54 30.6 ;
    END
  END dr_i[63]
  PIN dr_i[64]
    DIRECTION INPUT ;
    USE SIGNAL ;
    PORT
      LAYER M4 ;
        RECT  53.916 30.672 54 30.696 ;
    END
  END dr_i[64]
  PIN dr_i[65]
    DIRECTION INPUT ;
    USE SIGNAL ;
    PORT
      LAYER M4 ;
        RECT  53.916 30.768 54 30.792 ;
    END
  END dr_i[65]
  PIN dr_i[66]
    DIRECTION INPUT ;
    USE SIGNAL ;
    PORT
      LAYER M4 ;
        RECT  53.916 30.864 54 30.888 ;
    END
  END dr_i[66]
  PIN dr_i[67]
    DIRECTION INPUT ;
    USE SIGNAL ;
    PORT
      LAYER M4 ;
        RECT  53.916 30.96 54 30.984 ;
    END
  END dr_i[67]
  PIN dr_i[68]
    DIRECTION INPUT ;
    USE SIGNAL ;
    PORT
      LAYER M4 ;
        RECT  53.916 31.056 54 31.08 ;
    END
  END dr_i[68]
  PIN dr_i[69]
    DIRECTION INPUT ;
    USE SIGNAL ;
    PORT
      LAYER M4 ;
        RECT  53.916 31.152 54 31.176 ;
    END
  END dr_i[69]
  PIN dr_i[6]
    DIRECTION INPUT ;
    USE SIGNAL ;
    PORT
      LAYER M4 ;
        RECT  53.916 22.032 54 22.056 ;
    END
  END dr_i[6]
  PIN dr_i[70]
    DIRECTION INPUT ;
    USE SIGNAL ;
    PORT
      LAYER M4 ;
        RECT  53.916 31.248 54 31.272 ;
    END
  END dr_i[70]
  PIN dr_i[71]
    DIRECTION INPUT ;
    USE SIGNAL ;
    PORT
      LAYER M4 ;
        RECT  53.916 31.344 54 31.368 ;
    END
  END dr_i[71]
  PIN dr_i[72]
    DIRECTION INPUT ;
    USE SIGNAL ;
    PORT
      LAYER M4 ;
        RECT  53.916 31.44 54 31.464 ;
    END
  END dr_i[72]
  PIN dr_i[73]
    DIRECTION INPUT ;
    USE SIGNAL ;
    PORT
      LAYER M4 ;
        RECT  53.916 31.536 54 31.56 ;
    END
  END dr_i[73]
  PIN dr_i[74]
    DIRECTION INPUT ;
    USE SIGNAL ;
    PORT
      LAYER M4 ;
        RECT  53.916 31.632 54 31.656 ;
    END
  END dr_i[74]
  PIN dr_i[75]
    DIRECTION INPUT ;
    USE SIGNAL ;
    PORT
      LAYER M4 ;
        RECT  53.916 31.728 54 31.752 ;
    END
  END dr_i[75]
  PIN dr_i[76]
    DIRECTION INPUT ;
    USE SIGNAL ;
    PORT
      LAYER M4 ;
        RECT  53.916 31.824 54 31.848 ;
    END
  END dr_i[76]
  PIN dr_i[77]
    DIRECTION INPUT ;
    USE SIGNAL ;
    PORT
      LAYER M4 ;
        RECT  53.916 31.92 54 31.944 ;
    END
  END dr_i[77]
  PIN dr_i[78]
    DIRECTION INPUT ;
    USE SIGNAL ;
    PORT
      LAYER M4 ;
        RECT  53.916 32.016 54 32.04 ;
    END
  END dr_i[78]
  PIN dr_i[79]
    DIRECTION INPUT ;
    USE SIGNAL ;
    PORT
      LAYER M4 ;
        RECT  53.916 32.112 54 32.136 ;
    END
  END dr_i[79]
  PIN dr_i[7]
    DIRECTION INPUT ;
    USE SIGNAL ;
    PORT
      LAYER M4 ;
        RECT  53.916 22.128 54 22.152 ;
    END
  END dr_i[7]
  PIN dr_i[80]
    DIRECTION INPUT ;
    USE SIGNAL ;
    PORT
      LAYER M4 ;
        RECT  53.916 35.28 54 35.304 ;
    END
  END dr_i[80]
  PIN dr_i[81]
    DIRECTION INPUT ;
    USE SIGNAL ;
    PORT
      LAYER M4 ;
        RECT  53.916 35.376 54 35.4 ;
    END
  END dr_i[81]
  PIN dr_i[82]
    DIRECTION INPUT ;
    USE SIGNAL ;
    PORT
      LAYER M4 ;
        RECT  53.916 35.472 54 35.496 ;
    END
  END dr_i[82]
  PIN dr_i[83]
    DIRECTION INPUT ;
    USE SIGNAL ;
    PORT
      LAYER M4 ;
        RECT  53.916 35.568 54 35.592 ;
    END
  END dr_i[83]
  PIN dr_i[84]
    DIRECTION INPUT ;
    USE SIGNAL ;
    PORT
      LAYER M4 ;
        RECT  53.916 35.664 54 35.688 ;
    END
  END dr_i[84]
  PIN dr_i[85]
    DIRECTION INPUT ;
    USE SIGNAL ;
    PORT
      LAYER M4 ;
        RECT  53.916 35.76 54 35.784 ;
    END
  END dr_i[85]
  PIN dr_i[86]
    DIRECTION INPUT ;
    USE SIGNAL ;
    PORT
      LAYER M4 ;
        RECT  53.916 35.856 54 35.88 ;
    END
  END dr_i[86]
  PIN dr_i[87]
    DIRECTION INPUT ;
    USE SIGNAL ;
    PORT
      LAYER M4 ;
        RECT  53.916 35.952 54 35.976 ;
    END
  END dr_i[87]
  PIN dr_i[88]
    DIRECTION INPUT ;
    USE SIGNAL ;
    PORT
      LAYER M4 ;
        RECT  53.916 36.048 54 36.072 ;
    END
  END dr_i[88]
  PIN dr_i[89]
    DIRECTION INPUT ;
    USE SIGNAL ;
    PORT
      LAYER M4 ;
        RECT  53.916 36.144 54 36.168 ;
    END
  END dr_i[89]
  PIN dr_i[8]
    DIRECTION INPUT ;
    USE SIGNAL ;
    PORT
      LAYER M4 ;
        RECT  53.916 22.224 54 22.248 ;
    END
  END dr_i[8]
  PIN dr_i[90]
    DIRECTION INPUT ;
    USE SIGNAL ;
    PORT
      LAYER M4 ;
        RECT  53.916 36.24 54 36.264 ;
    END
  END dr_i[90]
  PIN dr_i[91]
    DIRECTION INPUT ;
    USE SIGNAL ;
    PORT
      LAYER M4 ;
        RECT  53.916 36.336 54 36.36 ;
    END
  END dr_i[91]
  PIN dr_i[92]
    DIRECTION INPUT ;
    USE SIGNAL ;
    PORT
      LAYER M4 ;
        RECT  53.916 36.432 54 36.456 ;
    END
  END dr_i[92]
  PIN dr_i[93]
    DIRECTION INPUT ;
    USE SIGNAL ;
    PORT
      LAYER M4 ;
        RECT  53.916 36.528 54 36.552 ;
    END
  END dr_i[93]
  PIN dr_i[94]
    DIRECTION INPUT ;
    USE SIGNAL ;
    PORT
      LAYER M4 ;
        RECT  53.916 36.624 54 36.648 ;
    END
  END dr_i[94]
  PIN dr_i[95]
    DIRECTION INPUT ;
    USE SIGNAL ;
    PORT
      LAYER M4 ;
        RECT  53.916 36.72 54 36.744 ;
    END
  END dr_i[95]
  PIN dr_i[96]
    DIRECTION INPUT ;
    USE SIGNAL ;
    PORT
      LAYER M4 ;
        RECT  53.916 36.816 54 36.84 ;
    END
  END dr_i[96]
  PIN dr_i[97]
    DIRECTION INPUT ;
    USE SIGNAL ;
    PORT
      LAYER M4 ;
        RECT  53.916 36.912 54 36.936 ;
    END
  END dr_i[97]
  PIN dr_i[98]
    DIRECTION INPUT ;
    USE SIGNAL ;
    PORT
      LAYER M4 ;
        RECT  53.916 37.008 54 37.032 ;
    END
  END dr_i[98]
  PIN dr_i[99]
    DIRECTION INPUT ;
    USE SIGNAL ;
    PORT
      LAYER M4 ;
        RECT  53.916 37.104 54 37.128 ;
    END
  END dr_i[99]
  PIN dr_i[9]
    DIRECTION INPUT ;
    USE SIGNAL ;
    PORT
      LAYER M4 ;
        RECT  53.916 22.32 54 22.344 ;
    END
  END dr_i[9]
  PIN dr_o[0]
    DIRECTION OUTPUT ;
    USE SIGNAL ;
    PORT
      LAYER M5 ;
        RECT  33.744 0 33.768 0.084 ;
    END
  END dr_o[0]
  PIN dr_o[100]
    DIRECTION OUTPUT ;
    USE SIGNAL ;
    PORT
      LAYER M5 ;
        RECT  31.056 0 31.08 0.084 ;
    END
  END dr_o[100]
  PIN dr_o[101]
    DIRECTION OUTPUT ;
    USE SIGNAL ;
    PORT
      LAYER M5 ;
        RECT  31.152 0 31.176 0.084 ;
    END
  END dr_o[101]
  PIN dr_o[102]
    DIRECTION OUTPUT ;
    USE SIGNAL ;
    PORT
      LAYER M5 ;
        RECT  31.248 0 31.272 0.084 ;
    END
  END dr_o[102]
  PIN dr_o[103]
    DIRECTION OUTPUT ;
    USE SIGNAL ;
    PORT
      LAYER M5 ;
        RECT  31.344 0 31.368 0.084 ;
    END
  END dr_o[103]
  PIN dr_o[104]
    DIRECTION OUTPUT ;
    USE SIGNAL ;
    PORT
      LAYER M5 ;
        RECT  31.44 0 31.464 0.084 ;
    END
  END dr_o[104]
  PIN dr_o[105]
    DIRECTION OUTPUT ;
    USE SIGNAL ;
    PORT
      LAYER M5 ;
        RECT  31.536 0 31.56 0.084 ;
    END
  END dr_o[105]
  PIN dr_o[106]
    DIRECTION OUTPUT ;
    USE SIGNAL ;
    PORT
      LAYER M5 ;
        RECT  31.632 0 31.656 0.084 ;
    END
  END dr_o[106]
  PIN dr_o[107]
    DIRECTION OUTPUT ;
    USE SIGNAL ;
    PORT
      LAYER M5 ;
        RECT  31.728 0 31.752 0.084 ;
    END
  END dr_o[107]
  PIN dr_o[108]
    DIRECTION OUTPUT ;
    USE SIGNAL ;
    PORT
      LAYER M5 ;
        RECT  31.824 0 31.848 0.084 ;
    END
  END dr_o[108]
  PIN dr_o[109]
    DIRECTION OUTPUT ;
    USE SIGNAL ;
    PORT
      LAYER M5 ;
        RECT  31.92 0 31.944 0.084 ;
    END
  END dr_o[109]
  PIN dr_o[10]
    DIRECTION OUTPUT ;
    USE SIGNAL ;
    PORT
      LAYER M5 ;
        RECT  34.704 0 34.728 0.084 ;
    END
  END dr_o[10]
  PIN dr_o[110]
    DIRECTION OUTPUT ;
    USE SIGNAL ;
    PORT
      LAYER M5 ;
        RECT  32.016 0 32.04 0.084 ;
    END
  END dr_o[110]
  PIN dr_o[111]
    DIRECTION OUTPUT ;
    USE SIGNAL ;
    PORT
      LAYER M5 ;
        RECT  32.112 0 32.136 0.084 ;
    END
  END dr_o[111]
  PIN dr_o[112]
    DIRECTION OUTPUT ;
    USE SIGNAL ;
    PORT
      LAYER M5 ;
        RECT  22.992 0 23.016 0.084 ;
    END
  END dr_o[112]
  PIN dr_o[113]
    DIRECTION OUTPUT ;
    USE SIGNAL ;
    PORT
      LAYER M5 ;
        RECT  23.088 0 23.112 0.084 ;
    END
  END dr_o[113]
  PIN dr_o[114]
    DIRECTION OUTPUT ;
    USE SIGNAL ;
    PORT
      LAYER M5 ;
        RECT  23.184 0 23.208 0.084 ;
    END
  END dr_o[114]
  PIN dr_o[115]
    DIRECTION OUTPUT ;
    USE SIGNAL ;
    PORT
      LAYER M5 ;
        RECT  23.28 0 23.304 0.084 ;
    END
  END dr_o[115]
  PIN dr_o[116]
    DIRECTION OUTPUT ;
    USE SIGNAL ;
    PORT
      LAYER M5 ;
        RECT  23.376 0 23.4 0.084 ;
    END
  END dr_o[116]
  PIN dr_o[117]
    DIRECTION OUTPUT ;
    USE SIGNAL ;
    PORT
      LAYER M5 ;
        RECT  23.472 0 23.496 0.084 ;
    END
  END dr_o[117]
  PIN dr_o[118]
    DIRECTION OUTPUT ;
    USE SIGNAL ;
    PORT
      LAYER M5 ;
        RECT  23.568 0 23.592 0.084 ;
    END
  END dr_o[118]
  PIN dr_o[119]
    DIRECTION OUTPUT ;
    USE SIGNAL ;
    PORT
      LAYER M5 ;
        RECT  23.664 0 23.688 0.084 ;
    END
  END dr_o[119]
  PIN dr_o[11]
    DIRECTION OUTPUT ;
    USE SIGNAL ;
    PORT
      LAYER M5 ;
        RECT  34.8 0 34.824 0.084 ;
    END
  END dr_o[11]
  PIN dr_o[120]
    DIRECTION OUTPUT ;
    USE SIGNAL ;
    PORT
      LAYER M5 ;
        RECT  23.76 0 23.784 0.084 ;
    END
  END dr_o[120]
  PIN dr_o[121]
    DIRECTION OUTPUT ;
    USE SIGNAL ;
    PORT
      LAYER M5 ;
        RECT  23.856 0 23.88 0.084 ;
    END
  END dr_o[121]
  PIN dr_o[122]
    DIRECTION OUTPUT ;
    USE SIGNAL ;
    PORT
      LAYER M5 ;
        RECT  23.952 0 23.976 0.084 ;
    END
  END dr_o[122]
  PIN dr_o[123]
    DIRECTION OUTPUT ;
    USE SIGNAL ;
    PORT
      LAYER M5 ;
        RECT  24.048 0 24.072 0.084 ;
    END
  END dr_o[123]
  PIN dr_o[124]
    DIRECTION OUTPUT ;
    USE SIGNAL ;
    PORT
      LAYER M5 ;
        RECT  24.144 0 24.168 0.084 ;
    END
  END dr_o[124]
  PIN dr_o[125]
    DIRECTION OUTPUT ;
    USE SIGNAL ;
    PORT
      LAYER M5 ;
        RECT  24.24 0 24.264 0.084 ;
    END
  END dr_o[125]
  PIN dr_o[126]
    DIRECTION OUTPUT ;
    USE SIGNAL ;
    PORT
      LAYER M5 ;
        RECT  24.336 0 24.36 0.084 ;
    END
  END dr_o[126]
  PIN dr_o[127]
    DIRECTION OUTPUT ;
    USE SIGNAL ;
    PORT
      LAYER M5 ;
        RECT  24.432 0 24.456 0.084 ;
    END
  END dr_o[127]
  PIN dr_o[128]
    DIRECTION OUTPUT ;
    USE SIGNAL ;
    PORT
      LAYER M5 ;
        RECT  24.528 0 24.552 0.084 ;
    END
  END dr_o[128]
  PIN dr_o[129]
    DIRECTION OUTPUT ;
    USE SIGNAL ;
    PORT
      LAYER M5 ;
        RECT  24.624 0 24.648 0.084 ;
    END
  END dr_o[129]
  PIN dr_o[12]
    DIRECTION OUTPUT ;
    USE SIGNAL ;
    PORT
      LAYER M5 ;
        RECT  34.896 0 34.92 0.084 ;
    END
  END dr_o[12]
  PIN dr_o[130]
    DIRECTION OUTPUT ;
    USE SIGNAL ;
    PORT
      LAYER M5 ;
        RECT  24.72 0 24.744 0.084 ;
    END
  END dr_o[130]
  PIN dr_o[131]
    DIRECTION OUTPUT ;
    USE SIGNAL ;
    PORT
      LAYER M5 ;
        RECT  24.816 0 24.84 0.084 ;
    END
  END dr_o[131]
  PIN dr_o[132]
    DIRECTION OUTPUT ;
    USE SIGNAL ;
    PORT
      LAYER M5 ;
        RECT  24.912 0 24.936 0.084 ;
    END
  END dr_o[132]
  PIN dr_o[133]
    DIRECTION OUTPUT ;
    USE SIGNAL ;
    PORT
      LAYER M5 ;
        RECT  25.008 0 25.032 0.084 ;
    END
  END dr_o[133]
  PIN dr_o[134]
    DIRECTION OUTPUT ;
    USE SIGNAL ;
    PORT
      LAYER M5 ;
        RECT  25.104 0 25.128 0.084 ;
    END
  END dr_o[134]
  PIN dr_o[135]
    DIRECTION OUTPUT ;
    USE SIGNAL ;
    PORT
      LAYER M5 ;
        RECT  25.2 0 25.224 0.084 ;
    END
  END dr_o[135]
  PIN dr_o[136]
    DIRECTION OUTPUT ;
    USE SIGNAL ;
    PORT
      LAYER M5 ;
        RECT  25.296 0 25.32 0.084 ;
    END
  END dr_o[136]
  PIN dr_o[137]
    DIRECTION OUTPUT ;
    USE SIGNAL ;
    PORT
      LAYER M5 ;
        RECT  25.392 0 25.416 0.084 ;
    END
  END dr_o[137]
  PIN dr_o[138]
    DIRECTION OUTPUT ;
    USE SIGNAL ;
    PORT
      LAYER M5 ;
        RECT  25.488 0 25.512 0.084 ;
    END
  END dr_o[138]
  PIN dr_o[139]
    DIRECTION OUTPUT ;
    USE SIGNAL ;
    PORT
      LAYER M5 ;
        RECT  25.584 0 25.608 0.084 ;
    END
  END dr_o[139]
  PIN dr_o[13]
    DIRECTION OUTPUT ;
    USE SIGNAL ;
    PORT
      LAYER M5 ;
        RECT  34.992 0 35.016 0.084 ;
    END
  END dr_o[13]
  PIN dr_o[140]
    DIRECTION OUTPUT ;
    USE SIGNAL ;
    PORT
      LAYER M5 ;
        RECT  25.68 0 25.704 0.084 ;
    END
  END dr_o[140]
  PIN dr_o[141]
    DIRECTION OUTPUT ;
    USE SIGNAL ;
    PORT
      LAYER M5 ;
        RECT  25.776 0 25.8 0.084 ;
    END
  END dr_o[141]
  PIN dr_o[142]
    DIRECTION OUTPUT ;
    USE SIGNAL ;
    PORT
      LAYER M5 ;
        RECT  25.872 0 25.896 0.084 ;
    END
  END dr_o[142]
  PIN dr_o[143]
    DIRECTION OUTPUT ;
    USE SIGNAL ;
    PORT
      LAYER M5 ;
        RECT  25.968 0 25.992 0.084 ;
    END
  END dr_o[143]
  PIN dr_o[144]
    DIRECTION OUTPUT ;
    USE SIGNAL ;
    PORT
      LAYER M5 ;
        RECT  26.064 0 26.088 0.084 ;
    END
  END dr_o[144]
  PIN dr_o[145]
    DIRECTION OUTPUT ;
    USE SIGNAL ;
    PORT
      LAYER M5 ;
        RECT  26.16 0 26.184 0.084 ;
    END
  END dr_o[145]
  PIN dr_o[146]
    DIRECTION OUTPUT ;
    USE SIGNAL ;
    PORT
      LAYER M5 ;
        RECT  26.256 0 26.28 0.084 ;
    END
  END dr_o[146]
  PIN dr_o[147]
    DIRECTION OUTPUT ;
    USE SIGNAL ;
    PORT
      LAYER M5 ;
        RECT  26.352 0 26.376 0.084 ;
    END
  END dr_o[147]
  PIN dr_o[148]
    DIRECTION OUTPUT ;
    USE SIGNAL ;
    PORT
      LAYER M5 ;
        RECT  26.448 0 26.472 0.084 ;
    END
  END dr_o[148]
  PIN dr_o[149]
    DIRECTION OUTPUT ;
    USE SIGNAL ;
    PORT
      LAYER M5 ;
        RECT  26.544 0 26.568 0.084 ;
    END
  END dr_o[149]
  PIN dr_o[14]
    DIRECTION OUTPUT ;
    USE SIGNAL ;
    PORT
      LAYER M5 ;
        RECT  35.088 0 35.112 0.084 ;
    END
  END dr_o[14]
  PIN dr_o[150]
    DIRECTION OUTPUT ;
    USE SIGNAL ;
    PORT
      LAYER M5 ;
        RECT  26.64 0 26.664 0.084 ;
    END
  END dr_o[150]
  PIN dr_o[151]
    DIRECTION OUTPUT ;
    USE SIGNAL ;
    PORT
      LAYER M5 ;
        RECT  26.736 0 26.76 0.084 ;
    END
  END dr_o[151]
  PIN dr_o[152]
    DIRECTION OUTPUT ;
    USE SIGNAL ;
    PORT
      LAYER M5 ;
        RECT  26.832 0 26.856 0.084 ;
    END
  END dr_o[152]
  PIN dr_o[153]
    DIRECTION OUTPUT ;
    USE SIGNAL ;
    PORT
      LAYER M5 ;
        RECT  26.928 0 26.952 0.084 ;
    END
  END dr_o[153]
  PIN dr_o[154]
    DIRECTION OUTPUT ;
    USE SIGNAL ;
    PORT
      LAYER M5 ;
        RECT  27.024 0 27.048 0.084 ;
    END
  END dr_o[154]
  PIN dr_o[155]
    DIRECTION OUTPUT ;
    USE SIGNAL ;
    PORT
      LAYER M5 ;
        RECT  27.12 0 27.144 0.084 ;
    END
  END dr_o[155]
  PIN dr_o[156]
    DIRECTION OUTPUT ;
    USE SIGNAL ;
    PORT
      LAYER M5 ;
        RECT  27.216 0 27.24 0.084 ;
    END
  END dr_o[156]
  PIN dr_o[157]
    DIRECTION OUTPUT ;
    USE SIGNAL ;
    PORT
      LAYER M5 ;
        RECT  27.312 0 27.336 0.084 ;
    END
  END dr_o[157]
  PIN dr_o[158]
    DIRECTION OUTPUT ;
    USE SIGNAL ;
    PORT
      LAYER M5 ;
        RECT  27.408 0 27.432 0.084 ;
    END
  END dr_o[158]
  PIN dr_o[159]
    DIRECTION OUTPUT ;
    USE SIGNAL ;
    PORT
      LAYER M5 ;
        RECT  27.504 0 27.528 0.084 ;
    END
  END dr_o[159]
  PIN dr_o[15]
    DIRECTION OUTPUT ;
    USE SIGNAL ;
    PORT
      LAYER M5 ;
        RECT  35.184 0 35.208 0.084 ;
    END
  END dr_o[15]
  PIN dr_o[160]
    DIRECTION OUTPUT ;
    USE SIGNAL ;
    PORT
      LAYER M5 ;
        RECT  27.6 0 27.624 0.084 ;
    END
  END dr_o[160]
  PIN dr_o[161]
    DIRECTION OUTPUT ;
    USE SIGNAL ;
    PORT
      LAYER M5 ;
        RECT  27.696 0 27.72 0.084 ;
    END
  END dr_o[161]
  PIN dr_o[162]
    DIRECTION OUTPUT ;
    USE SIGNAL ;
    PORT
      LAYER M5 ;
        RECT  27.792 0 27.816 0.084 ;
    END
  END dr_o[162]
  PIN dr_o[163]
    DIRECTION OUTPUT ;
    USE SIGNAL ;
    PORT
      LAYER M5 ;
        RECT  27.888 0 27.912 0.084 ;
    END
  END dr_o[163]
  PIN dr_o[164]
    DIRECTION OUTPUT ;
    USE SIGNAL ;
    PORT
      LAYER M5 ;
        RECT  27.984 0 28.008 0.084 ;
    END
  END dr_o[164]
  PIN dr_o[165]
    DIRECTION OUTPUT ;
    USE SIGNAL ;
    PORT
      LAYER M5 ;
        RECT  28.08 0 28.104 0.084 ;
    END
  END dr_o[165]
  PIN dr_o[166]
    DIRECTION OUTPUT ;
    USE SIGNAL ;
    PORT
      LAYER M5 ;
        RECT  28.176 0 28.2 0.084 ;
    END
  END dr_o[166]
  PIN dr_o[167]
    DIRECTION OUTPUT ;
    USE SIGNAL ;
    PORT
      LAYER M5 ;
        RECT  28.272 0 28.296 0.084 ;
    END
  END dr_o[167]
  PIN dr_o[168]
    DIRECTION OUTPUT ;
    USE SIGNAL ;
    PORT
      LAYER M5 ;
        RECT  28.368 0 28.392 0.084 ;
    END
  END dr_o[168]
  PIN dr_o[169]
    DIRECTION OUTPUT ;
    USE SIGNAL ;
    PORT
      LAYER M5 ;
        RECT  28.464 0 28.488 0.084 ;
    END
  END dr_o[169]
  PIN dr_o[16]
    DIRECTION OUTPUT ;
    USE SIGNAL ;
    PORT
      LAYER M5 ;
        RECT  35.28 0 35.304 0.084 ;
    END
  END dr_o[16]
  PIN dr_o[170]
    DIRECTION OUTPUT ;
    USE SIGNAL ;
    PORT
      LAYER M5 ;
        RECT  28.56 0 28.584 0.084 ;
    END
  END dr_o[170]
  PIN dr_o[171]
    DIRECTION OUTPUT ;
    USE SIGNAL ;
    PORT
      LAYER M5 ;
        RECT  28.656 0 28.68 0.084 ;
    END
  END dr_o[171]
  PIN dr_o[172]
    DIRECTION OUTPUT ;
    USE SIGNAL ;
    PORT
      LAYER M5 ;
        RECT  28.752 0 28.776 0.084 ;
    END
  END dr_o[172]
  PIN dr_o[173]
    DIRECTION OUTPUT ;
    USE SIGNAL ;
    PORT
      LAYER M5 ;
        RECT  28.848 0 28.872 0.084 ;
    END
  END dr_o[173]
  PIN dr_o[174]
    DIRECTION OUTPUT ;
    USE SIGNAL ;
    PORT
      LAYER M5 ;
        RECT  28.944 0 28.968 0.084 ;
    END
  END dr_o[174]
  PIN dr_o[175]
    DIRECTION OUTPUT ;
    USE SIGNAL ;
    PORT
      LAYER M5 ;
        RECT  29.04 0 29.064 0.084 ;
    END
  END dr_o[175]
  PIN dr_o[176]
    DIRECTION OUTPUT ;
    USE SIGNAL ;
    PORT
      LAYER M5 ;
        RECT  16.08 0 16.104 0.084 ;
    END
  END dr_o[176]
  PIN dr_o[177]
    DIRECTION OUTPUT ;
    USE SIGNAL ;
    PORT
      LAYER M5 ;
        RECT  16.176 0 16.2 0.084 ;
    END
  END dr_o[177]
  PIN dr_o[178]
    DIRECTION OUTPUT ;
    USE SIGNAL ;
    PORT
      LAYER M5 ;
        RECT  16.272 0 16.296 0.084 ;
    END
  END dr_o[178]
  PIN dr_o[179]
    DIRECTION OUTPUT ;
    USE SIGNAL ;
    PORT
      LAYER M5 ;
        RECT  16.368 0 16.392 0.084 ;
    END
  END dr_o[179]
  PIN dr_o[17]
    DIRECTION OUTPUT ;
    USE SIGNAL ;
    PORT
      LAYER M5 ;
        RECT  35.376 0 35.4 0.084 ;
    END
  END dr_o[17]
  PIN dr_o[180]
    DIRECTION OUTPUT ;
    USE SIGNAL ;
    PORT
      LAYER M5 ;
        RECT  16.464 0 16.488 0.084 ;
    END
  END dr_o[180]
  PIN dr_o[181]
    DIRECTION OUTPUT ;
    USE SIGNAL ;
    PORT
      LAYER M5 ;
        RECT  16.56 0 16.584 0.084 ;
    END
  END dr_o[181]
  PIN dr_o[182]
    DIRECTION OUTPUT ;
    USE SIGNAL ;
    PORT
      LAYER M5 ;
        RECT  16.656 0 16.68 0.084 ;
    END
  END dr_o[182]
  PIN dr_o[183]
    DIRECTION OUTPUT ;
    USE SIGNAL ;
    PORT
      LAYER M5 ;
        RECT  16.752 0 16.776 0.084 ;
    END
  END dr_o[183]
  PIN dr_o[184]
    DIRECTION OUTPUT ;
    USE SIGNAL ;
    PORT
      LAYER M5 ;
        RECT  16.848 0 16.872 0.084 ;
    END
  END dr_o[184]
  PIN dr_o[185]
    DIRECTION OUTPUT ;
    USE SIGNAL ;
    PORT
      LAYER M5 ;
        RECT  16.944 0 16.968 0.084 ;
    END
  END dr_o[185]
  PIN dr_o[186]
    DIRECTION OUTPUT ;
    USE SIGNAL ;
    PORT
      LAYER M5 ;
        RECT  17.04 0 17.064 0.084 ;
    END
  END dr_o[186]
  PIN dr_o[187]
    DIRECTION OUTPUT ;
    USE SIGNAL ;
    PORT
      LAYER M5 ;
        RECT  17.136 0 17.16 0.084 ;
    END
  END dr_o[187]
  PIN dr_o[188]
    DIRECTION OUTPUT ;
    USE SIGNAL ;
    PORT
      LAYER M5 ;
        RECT  17.232 0 17.256 0.084 ;
    END
  END dr_o[188]
  PIN dr_o[189]
    DIRECTION OUTPUT ;
    USE SIGNAL ;
    PORT
      LAYER M5 ;
        RECT  17.328 0 17.352 0.084 ;
    END
  END dr_o[189]
  PIN dr_o[18]
    DIRECTION OUTPUT ;
    USE SIGNAL ;
    PORT
      LAYER M5 ;
        RECT  35.472 0 35.496 0.084 ;
    END
  END dr_o[18]
  PIN dr_o[190]
    DIRECTION OUTPUT ;
    USE SIGNAL ;
    PORT
      LAYER M5 ;
        RECT  17.424 0 17.448 0.084 ;
    END
  END dr_o[190]
  PIN dr_o[191]
    DIRECTION OUTPUT ;
    USE SIGNAL ;
    PORT
      LAYER M5 ;
        RECT  17.52 0 17.544 0.084 ;
    END
  END dr_o[191]
  PIN dr_o[192]
    DIRECTION OUTPUT ;
    USE SIGNAL ;
    PORT
      LAYER M5 ;
        RECT  17.616 0 17.64 0.084 ;
    END
  END dr_o[192]
  PIN dr_o[193]
    DIRECTION OUTPUT ;
    USE SIGNAL ;
    PORT
      LAYER M5 ;
        RECT  17.712 0 17.736 0.084 ;
    END
  END dr_o[193]
  PIN dr_o[194]
    DIRECTION OUTPUT ;
    USE SIGNAL ;
    PORT
      LAYER M5 ;
        RECT  17.808 0 17.832 0.084 ;
    END
  END dr_o[194]
  PIN dr_o[195]
    DIRECTION OUTPUT ;
    USE SIGNAL ;
    PORT
      LAYER M5 ;
        RECT  17.904 0 17.928 0.084 ;
    END
  END dr_o[195]
  PIN dr_o[196]
    DIRECTION OUTPUT ;
    USE SIGNAL ;
    PORT
      LAYER M5 ;
        RECT  18 0 18.024 0.084 ;
    END
  END dr_o[196]
  PIN dr_o[197]
    DIRECTION OUTPUT ;
    USE SIGNAL ;
    PORT
      LAYER M5 ;
        RECT  18.096 0 18.12 0.084 ;
    END
  END dr_o[197]
  PIN dr_o[198]
    DIRECTION OUTPUT ;
    USE SIGNAL ;
    PORT
      LAYER M5 ;
        RECT  18.192 0 18.216 0.084 ;
    END
  END dr_o[198]
  PIN dr_o[199]
    DIRECTION OUTPUT ;
    USE SIGNAL ;
    PORT
      LAYER M5 ;
        RECT  18.288 0 18.312 0.084 ;
    END
  END dr_o[199]
  PIN dr_o[19]
    DIRECTION OUTPUT ;
    USE SIGNAL ;
    PORT
      LAYER M5 ;
        RECT  35.568 0 35.592 0.084 ;
    END
  END dr_o[19]
  PIN dr_o[1]
    DIRECTION OUTPUT ;
    USE SIGNAL ;
    PORT
      LAYER M5 ;
        RECT  33.84 0 33.864 0.084 ;
    END
  END dr_o[1]
  PIN dr_o[200]
    DIRECTION OUTPUT ;
    USE SIGNAL ;
    PORT
      LAYER M5 ;
        RECT  18.384 0 18.408 0.084 ;
    END
  END dr_o[200]
  PIN dr_o[201]
    DIRECTION OUTPUT ;
    USE SIGNAL ;
    PORT
      LAYER M5 ;
        RECT  18.48 0 18.504 0.084 ;
    END
  END dr_o[201]
  PIN dr_o[202]
    DIRECTION OUTPUT ;
    USE SIGNAL ;
    PORT
      LAYER M5 ;
        RECT  18.576 0 18.6 0.084 ;
    END
  END dr_o[202]
  PIN dr_o[203]
    DIRECTION OUTPUT ;
    USE SIGNAL ;
    PORT
      LAYER M5 ;
        RECT  18.672 0 18.696 0.084 ;
    END
  END dr_o[203]
  PIN dr_o[204]
    DIRECTION OUTPUT ;
    USE SIGNAL ;
    PORT
      LAYER M5 ;
        RECT  18.768 0 18.792 0.084 ;
    END
  END dr_o[204]
  PIN dr_o[205]
    DIRECTION OUTPUT ;
    USE SIGNAL ;
    PORT
      LAYER M5 ;
        RECT  18.864 0 18.888 0.084 ;
    END
  END dr_o[205]
  PIN dr_o[206]
    DIRECTION OUTPUT ;
    USE SIGNAL ;
    PORT
      LAYER M5 ;
        RECT  18.96 0 18.984 0.084 ;
    END
  END dr_o[206]
  PIN dr_o[207]
    DIRECTION OUTPUT ;
    USE SIGNAL ;
    PORT
      LAYER M5 ;
        RECT  19.056 0 19.08 0.084 ;
    END
  END dr_o[207]
  PIN dr_o[208]
    DIRECTION OUTPUT ;
    USE SIGNAL ;
    PORT
      LAYER M5 ;
        RECT  39.12 0 39.144 0.084 ;
    END
  END dr_o[208]
  PIN dr_o[209]
    DIRECTION OUTPUT ;
    USE SIGNAL ;
    PORT
      LAYER M5 ;
        RECT  39.216 0 39.24 0.084 ;
    END
  END dr_o[209]
  PIN dr_o[20]
    DIRECTION OUTPUT ;
    USE SIGNAL ;
    PORT
      LAYER M5 ;
        RECT  35.664 0 35.688 0.084 ;
    END
  END dr_o[20]
  PIN dr_o[210]
    DIRECTION OUTPUT ;
    USE SIGNAL ;
    PORT
      LAYER M5 ;
        RECT  39.312 0 39.336 0.084 ;
    END
  END dr_o[210]
  PIN dr_o[211]
    DIRECTION OUTPUT ;
    USE SIGNAL ;
    PORT
      LAYER M5 ;
        RECT  39.408 0 39.432 0.084 ;
    END
  END dr_o[211]
  PIN dr_o[212]
    DIRECTION OUTPUT ;
    USE SIGNAL ;
    PORT
      LAYER M5 ;
        RECT  39.504 0 39.528 0.084 ;
    END
  END dr_o[212]
  PIN dr_o[213]
    DIRECTION OUTPUT ;
    USE SIGNAL ;
    PORT
      LAYER M5 ;
        RECT  39.6 0 39.624 0.084 ;
    END
  END dr_o[213]
  PIN dr_o[214]
    DIRECTION OUTPUT ;
    USE SIGNAL ;
    PORT
      LAYER M5 ;
        RECT  39.696 0 39.72 0.084 ;
    END
  END dr_o[214]
  PIN dr_o[215]
    DIRECTION OUTPUT ;
    USE SIGNAL ;
    PORT
      LAYER M5 ;
        RECT  39.792 0 39.816 0.084 ;
    END
  END dr_o[215]
  PIN dr_o[216]
    DIRECTION OUTPUT ;
    USE SIGNAL ;
    PORT
      LAYER M5 ;
        RECT  39.888 0 39.912 0.084 ;
    END
  END dr_o[216]
  PIN dr_o[21]
    DIRECTION OUTPUT ;
    USE SIGNAL ;
    PORT
      LAYER M5 ;
        RECT  35.76 0 35.784 0.084 ;
    END
  END dr_o[21]
  PIN dr_o[22]
    DIRECTION OUTPUT ;
    USE SIGNAL ;
    PORT
      LAYER M5 ;
        RECT  35.856 0 35.88 0.084 ;
    END
  END dr_o[22]
  PIN dr_o[23]
    DIRECTION OUTPUT ;
    USE SIGNAL ;
    PORT
      LAYER M5 ;
        RECT  35.952 0 35.976 0.084 ;
    END
  END dr_o[23]
  PIN dr_o[24]
    DIRECTION OUTPUT ;
    USE SIGNAL ;
    PORT
      LAYER M5 ;
        RECT  36.048 0 36.072 0.084 ;
    END
  END dr_o[24]
  PIN dr_o[25]
    DIRECTION OUTPUT ;
    USE SIGNAL ;
    PORT
      LAYER M5 ;
        RECT  36.144 0 36.168 0.084 ;
    END
  END dr_o[25]
  PIN dr_o[26]
    DIRECTION OUTPUT ;
    USE SIGNAL ;
    PORT
      LAYER M5 ;
        RECT  36.24 0 36.264 0.084 ;
    END
  END dr_o[26]
  PIN dr_o[27]
    DIRECTION OUTPUT ;
    USE SIGNAL ;
    PORT
      LAYER M5 ;
        RECT  36.336 0 36.36 0.084 ;
    END
  END dr_o[27]
  PIN dr_o[28]
    DIRECTION OUTPUT ;
    USE SIGNAL ;
    PORT
      LAYER M5 ;
        RECT  36.432 0 36.456 0.084 ;
    END
  END dr_o[28]
  PIN dr_o[29]
    DIRECTION OUTPUT ;
    USE SIGNAL ;
    PORT
      LAYER M5 ;
        RECT  36.528 0 36.552 0.084 ;
    END
  END dr_o[29]
  PIN dr_o[2]
    DIRECTION OUTPUT ;
    USE SIGNAL ;
    PORT
      LAYER M5 ;
        RECT  33.936 0 33.96 0.084 ;
    END
  END dr_o[2]
  PIN dr_o[30]
    DIRECTION OUTPUT ;
    USE SIGNAL ;
    PORT
      LAYER M5 ;
        RECT  36.624 0 36.648 0.084 ;
    END
  END dr_o[30]
  PIN dr_o[31]
    DIRECTION OUTPUT ;
    USE SIGNAL ;
    PORT
      LAYER M5 ;
        RECT  36.72 0 36.744 0.084 ;
    END
  END dr_o[31]
  PIN dr_o[32]
    DIRECTION OUTPUT ;
    USE SIGNAL ;
    PORT
      LAYER M5 ;
        RECT  36.816 0 36.84 0.084 ;
    END
  END dr_o[32]
  PIN dr_o[33]
    DIRECTION OUTPUT ;
    USE SIGNAL ;
    PORT
      LAYER M5 ;
        RECT  36.912 0 36.936 0.084 ;
    END
  END dr_o[33]
  PIN dr_o[34]
    DIRECTION OUTPUT ;
    USE SIGNAL ;
    PORT
      LAYER M5 ;
        RECT  37.008 0 37.032 0.084 ;
    END
  END dr_o[34]
  PIN dr_o[35]
    DIRECTION OUTPUT ;
    USE SIGNAL ;
    PORT
      LAYER M5 ;
        RECT  37.104 0 37.128 0.084 ;
    END
  END dr_o[35]
  PIN dr_o[36]
    DIRECTION OUTPUT ;
    USE SIGNAL ;
    PORT
      LAYER M5 ;
        RECT  37.2 0 37.224 0.084 ;
    END
  END dr_o[36]
  PIN dr_o[37]
    DIRECTION OUTPUT ;
    USE SIGNAL ;
    PORT
      LAYER M5 ;
        RECT  37.296 0 37.32 0.084 ;
    END
  END dr_o[37]
  PIN dr_o[38]
    DIRECTION OUTPUT ;
    USE SIGNAL ;
    PORT
      LAYER M5 ;
        RECT  37.392 0 37.416 0.084 ;
    END
  END dr_o[38]
  PIN dr_o[39]
    DIRECTION OUTPUT ;
    USE SIGNAL ;
    PORT
      LAYER M5 ;
        RECT  37.488 0 37.512 0.084 ;
    END
  END dr_o[39]
  PIN dr_o[3]
    DIRECTION OUTPUT ;
    USE SIGNAL ;
    PORT
      LAYER M5 ;
        RECT  34.032 0 34.056 0.084 ;
    END
  END dr_o[3]
  PIN dr_o[40]
    DIRECTION OUTPUT ;
    USE SIGNAL ;
    PORT
      LAYER M5 ;
        RECT  37.584 0 37.608 0.084 ;
    END
  END dr_o[40]
  PIN dr_o[41]
    DIRECTION OUTPUT ;
    USE SIGNAL ;
    PORT
      LAYER M5 ;
        RECT  37.68 0 37.704 0.084 ;
    END
  END dr_o[41]
  PIN dr_o[42]
    DIRECTION OUTPUT ;
    USE SIGNAL ;
    PORT
      LAYER M5 ;
        RECT  37.776 0 37.8 0.084 ;
    END
  END dr_o[42]
  PIN dr_o[43]
    DIRECTION OUTPUT ;
    USE SIGNAL ;
    PORT
      LAYER M5 ;
        RECT  37.872 0 37.896 0.084 ;
    END
  END dr_o[43]
  PIN dr_o[44]
    DIRECTION OUTPUT ;
    USE SIGNAL ;
    PORT
      LAYER M5 ;
        RECT  37.968 0 37.992 0.084 ;
    END
  END dr_o[44]
  PIN dr_o[45]
    DIRECTION OUTPUT ;
    USE SIGNAL ;
    PORT
      LAYER M5 ;
        RECT  38.064 0 38.088 0.084 ;
    END
  END dr_o[45]
  PIN dr_o[46]
    DIRECTION OUTPUT ;
    USE SIGNAL ;
    PORT
      LAYER M5 ;
        RECT  38.16 0 38.184 0.084 ;
    END
  END dr_o[46]
  PIN dr_o[47]
    DIRECTION OUTPUT ;
    USE SIGNAL ;
    PORT
      LAYER M5 ;
        RECT  38.256 0 38.28 0.084 ;
    END
  END dr_o[47]
  PIN dr_o[48]
    DIRECTION OUTPUT ;
    USE SIGNAL ;
    PORT
      LAYER M5 ;
        RECT  19.92 0 19.944 0.084 ;
    END
  END dr_o[48]
  PIN dr_o[49]
    DIRECTION OUTPUT ;
    USE SIGNAL ;
    PORT
      LAYER M5 ;
        RECT  20.016 0 20.04 0.084 ;
    END
  END dr_o[49]
  PIN dr_o[4]
    DIRECTION OUTPUT ;
    USE SIGNAL ;
    PORT
      LAYER M5 ;
        RECT  34.128 0 34.152 0.084 ;
    END
  END dr_o[4]
  PIN dr_o[50]
    DIRECTION OUTPUT ;
    USE SIGNAL ;
    PORT
      LAYER M5 ;
        RECT  20.112 0 20.136 0.084 ;
    END
  END dr_o[50]
  PIN dr_o[51]
    DIRECTION OUTPUT ;
    USE SIGNAL ;
    PORT
      LAYER M5 ;
        RECT  20.208 0 20.232 0.084 ;
    END
  END dr_o[51]
  PIN dr_o[52]
    DIRECTION OUTPUT ;
    USE SIGNAL ;
    PORT
      LAYER M5 ;
        RECT  20.304 0 20.328 0.084 ;
    END
  END dr_o[52]
  PIN dr_o[53]
    DIRECTION OUTPUT ;
    USE SIGNAL ;
    PORT
      LAYER M5 ;
        RECT  20.4 0 20.424 0.084 ;
    END
  END dr_o[53]
  PIN dr_o[54]
    DIRECTION OUTPUT ;
    USE SIGNAL ;
    PORT
      LAYER M5 ;
        RECT  20.496 0 20.52 0.084 ;
    END
  END dr_o[54]
  PIN dr_o[55]
    DIRECTION OUTPUT ;
    USE SIGNAL ;
    PORT
      LAYER M5 ;
        RECT  20.592 0 20.616 0.084 ;
    END
  END dr_o[55]
  PIN dr_o[56]
    DIRECTION OUTPUT ;
    USE SIGNAL ;
    PORT
      LAYER M5 ;
        RECT  20.688 0 20.712 0.084 ;
    END
  END dr_o[56]
  PIN dr_o[57]
    DIRECTION OUTPUT ;
    USE SIGNAL ;
    PORT
      LAYER M5 ;
        RECT  20.784 0 20.808 0.084 ;
    END
  END dr_o[57]
  PIN dr_o[58]
    DIRECTION OUTPUT ;
    USE SIGNAL ;
    PORT
      LAYER M5 ;
        RECT  20.88 0 20.904 0.084 ;
    END
  END dr_o[58]
  PIN dr_o[59]
    DIRECTION OUTPUT ;
    USE SIGNAL ;
    PORT
      LAYER M5 ;
        RECT  20.976 0 21 0.084 ;
    END
  END dr_o[59]
  PIN dr_o[5]
    DIRECTION OUTPUT ;
    USE SIGNAL ;
    PORT
      LAYER M5 ;
        RECT  34.224 0 34.248 0.084 ;
    END
  END dr_o[5]
  PIN dr_o[60]
    DIRECTION OUTPUT ;
    USE SIGNAL ;
    PORT
      LAYER M5 ;
        RECT  21.072 0 21.096 0.084 ;
    END
  END dr_o[60]
  PIN dr_o[61]
    DIRECTION OUTPUT ;
    USE SIGNAL ;
    PORT
      LAYER M5 ;
        RECT  21.168 0 21.192 0.084 ;
    END
  END dr_o[61]
  PIN dr_o[62]
    DIRECTION OUTPUT ;
    USE SIGNAL ;
    PORT
      LAYER M5 ;
        RECT  21.264 0 21.288 0.084 ;
    END
  END dr_o[62]
  PIN dr_o[63]
    DIRECTION OUTPUT ;
    USE SIGNAL ;
    PORT
      LAYER M5 ;
        RECT  21.36 0 21.384 0.084 ;
    END
  END dr_o[63]
  PIN dr_o[64]
    DIRECTION OUTPUT ;
    USE SIGNAL ;
    PORT
      LAYER M5 ;
        RECT  21.456 0 21.48 0.084 ;
    END
  END dr_o[64]
  PIN dr_o[65]
    DIRECTION OUTPUT ;
    USE SIGNAL ;
    PORT
      LAYER M5 ;
        RECT  21.552 0 21.576 0.084 ;
    END
  END dr_o[65]
  PIN dr_o[66]
    DIRECTION OUTPUT ;
    USE SIGNAL ;
    PORT
      LAYER M5 ;
        RECT  21.648 0 21.672 0.084 ;
    END
  END dr_o[66]
  PIN dr_o[67]
    DIRECTION OUTPUT ;
    USE SIGNAL ;
    PORT
      LAYER M5 ;
        RECT  21.744 0 21.768 0.084 ;
    END
  END dr_o[67]
  PIN dr_o[68]
    DIRECTION OUTPUT ;
    USE SIGNAL ;
    PORT
      LAYER M5 ;
        RECT  21.84 0 21.864 0.084 ;
    END
  END dr_o[68]
  PIN dr_o[69]
    DIRECTION OUTPUT ;
    USE SIGNAL ;
    PORT
      LAYER M5 ;
        RECT  21.936 0 21.96 0.084 ;
    END
  END dr_o[69]
  PIN dr_o[6]
    DIRECTION OUTPUT ;
    USE SIGNAL ;
    PORT
      LAYER M5 ;
        RECT  34.32 0 34.344 0.084 ;
    END
  END dr_o[6]
  PIN dr_o[70]
    DIRECTION OUTPUT ;
    USE SIGNAL ;
    PORT
      LAYER M5 ;
        RECT  22.032 0 22.056 0.084 ;
    END
  END dr_o[70]
  PIN dr_o[71]
    DIRECTION OUTPUT ;
    USE SIGNAL ;
    PORT
      LAYER M5 ;
        RECT  22.128 0 22.152 0.084 ;
    END
  END dr_o[71]
  PIN dr_o[72]
    DIRECTION OUTPUT ;
    USE SIGNAL ;
    PORT
      LAYER M5 ;
        RECT  22.224 0 22.248 0.084 ;
    END
  END dr_o[72]
  PIN dr_o[73]
    DIRECTION OUTPUT ;
    USE SIGNAL ;
    PORT
      LAYER M5 ;
        RECT  22.32 0 22.344 0.084 ;
    END
  END dr_o[73]
  PIN dr_o[74]
    DIRECTION OUTPUT ;
    USE SIGNAL ;
    PORT
      LAYER M5 ;
        RECT  22.416 0 22.44 0.084 ;
    END
  END dr_o[74]
  PIN dr_o[75]
    DIRECTION OUTPUT ;
    USE SIGNAL ;
    PORT
      LAYER M5 ;
        RECT  22.512 0 22.536 0.084 ;
    END
  END dr_o[75]
  PIN dr_o[76]
    DIRECTION OUTPUT ;
    USE SIGNAL ;
    PORT
      LAYER M5 ;
        RECT  22.608 0 22.632 0.084 ;
    END
  END dr_o[76]
  PIN dr_o[77]
    DIRECTION OUTPUT ;
    USE SIGNAL ;
    PORT
      LAYER M5 ;
        RECT  22.704 0 22.728 0.084 ;
    END
  END dr_o[77]
  PIN dr_o[78]
    DIRECTION OUTPUT ;
    USE SIGNAL ;
    PORT
      LAYER M5 ;
        RECT  22.8 0 22.824 0.084 ;
    END
  END dr_o[78]
  PIN dr_o[79]
    DIRECTION OUTPUT ;
    USE SIGNAL ;
    PORT
      LAYER M5 ;
        RECT  22.896 0 22.92 0.084 ;
    END
  END dr_o[79]
  PIN dr_o[7]
    DIRECTION OUTPUT ;
    USE SIGNAL ;
    PORT
      LAYER M5 ;
        RECT  34.416 0 34.44 0.084 ;
    END
  END dr_o[7]
  PIN dr_o[80]
    DIRECTION OUTPUT ;
    USE SIGNAL ;
    PORT
      LAYER M5 ;
        RECT  29.136 0 29.16 0.084 ;
    END
  END dr_o[80]
  PIN dr_o[81]
    DIRECTION OUTPUT ;
    USE SIGNAL ;
    PORT
      LAYER M5 ;
        RECT  29.232 0 29.256 0.084 ;
    END
  END dr_o[81]
  PIN dr_o[82]
    DIRECTION OUTPUT ;
    USE SIGNAL ;
    PORT
      LAYER M5 ;
        RECT  29.328 0 29.352 0.084 ;
    END
  END dr_o[82]
  PIN dr_o[83]
    DIRECTION OUTPUT ;
    USE SIGNAL ;
    PORT
      LAYER M5 ;
        RECT  29.424 0 29.448 0.084 ;
    END
  END dr_o[83]
  PIN dr_o[84]
    DIRECTION OUTPUT ;
    USE SIGNAL ;
    PORT
      LAYER M5 ;
        RECT  29.52 0 29.544 0.084 ;
    END
  END dr_o[84]
  PIN dr_o[85]
    DIRECTION OUTPUT ;
    USE SIGNAL ;
    PORT
      LAYER M5 ;
        RECT  29.616 0 29.64 0.084 ;
    END
  END dr_o[85]
  PIN dr_o[86]
    DIRECTION OUTPUT ;
    USE SIGNAL ;
    PORT
      LAYER M5 ;
        RECT  29.712 0 29.736 0.084 ;
    END
  END dr_o[86]
  PIN dr_o[87]
    DIRECTION OUTPUT ;
    USE SIGNAL ;
    PORT
      LAYER M5 ;
        RECT  29.808 0 29.832 0.084 ;
    END
  END dr_o[87]
  PIN dr_o[88]
    DIRECTION OUTPUT ;
    USE SIGNAL ;
    PORT
      LAYER M5 ;
        RECT  29.904 0 29.928 0.084 ;
    END
  END dr_o[88]
  PIN dr_o[89]
    DIRECTION OUTPUT ;
    USE SIGNAL ;
    PORT
      LAYER M5 ;
        RECT  30 0 30.024 0.084 ;
    END
  END dr_o[89]
  PIN dr_o[8]
    DIRECTION OUTPUT ;
    USE SIGNAL ;
    PORT
      LAYER M5 ;
        RECT  34.512 0 34.536 0.084 ;
    END
  END dr_o[8]
  PIN dr_o[90]
    DIRECTION OUTPUT ;
    USE SIGNAL ;
    PORT
      LAYER M5 ;
        RECT  30.096 0 30.12 0.084 ;
    END
  END dr_o[90]
  PIN dr_o[91]
    DIRECTION OUTPUT ;
    USE SIGNAL ;
    PORT
      LAYER M5 ;
        RECT  30.192 0 30.216 0.084 ;
    END
  END dr_o[91]
  PIN dr_o[92]
    DIRECTION OUTPUT ;
    USE SIGNAL ;
    PORT
      LAYER M5 ;
        RECT  30.288 0 30.312 0.084 ;
    END
  END dr_o[92]
  PIN dr_o[93]
    DIRECTION OUTPUT ;
    USE SIGNAL ;
    PORT
      LAYER M5 ;
        RECT  30.384 0 30.408 0.084 ;
    END
  END dr_o[93]
  PIN dr_o[94]
    DIRECTION OUTPUT ;
    USE SIGNAL ;
    PORT
      LAYER M5 ;
        RECT  30.48 0 30.504 0.084 ;
    END
  END dr_o[94]
  PIN dr_o[95]
    DIRECTION OUTPUT ;
    USE SIGNAL ;
    PORT
      LAYER M5 ;
        RECT  30.576 0 30.6 0.084 ;
    END
  END dr_o[95]
  PIN dr_o[96]
    DIRECTION OUTPUT ;
    USE SIGNAL ;
    PORT
      LAYER M5 ;
        RECT  30.672 0 30.696 0.084 ;
    END
  END dr_o[96]
  PIN dr_o[97]
    DIRECTION OUTPUT ;
    USE SIGNAL ;
    PORT
      LAYER M5 ;
        RECT  30.768 0 30.792 0.084 ;
    END
  END dr_o[97]
  PIN dr_o[98]
    DIRECTION OUTPUT ;
    USE SIGNAL ;
    PORT
      LAYER M5 ;
        RECT  30.864 0 30.888 0.084 ;
    END
  END dr_o[98]
  PIN dr_o[99]
    DIRECTION OUTPUT ;
    USE SIGNAL ;
    PORT
      LAYER M5 ;
        RECT  30.96 0 30.984 0.084 ;
    END
  END dr_o[99]
  PIN dr_o[9]
    DIRECTION OUTPUT ;
    USE SIGNAL ;
    PORT
      LAYER M5 ;
        RECT  34.608 0 34.632 0.084 ;
    END
  END dr_o[9]
  PIN lane_rst_n
    DIRECTION OUTPUT ;
    USE SIGNAL ;
    PORT
      LAYER M5 ;
        RECT  39.984 0 40.008 0.084 ;
    END
  END lane_rst_n
  PIN rst_n
    DIRECTION INPUT ;
    USE SIGNAL ;
    PORT
      LAYER M4 ;
        RECT  0 20.496 0.084 20.52 ;
    END
  END rst_n
  PIN VDD
    DIRECTION INOUT ;
    USE POWER ;
    PORT
      LAYER M5 ;
        RECT  51.192 2.151 51.312 41.049 ;
        RECT  45.792 2.151 45.912 41.049 ;
        RECT  40.392 2.151 40.512 41.049 ;
        RECT  34.992 2.151 35.112 41.049 ;
        RECT  29.592 2.151 29.712 41.049 ;
        RECT  24.192 2.151 24.312 41.049 ;
        RECT  18.792 2.151 18.912 41.049 ;
        RECT  13.392 2.151 13.512 41.049 ;
        RECT  7.992 2.151 8.112 41.049 ;
        RECT  2.592 2.151 2.712 41.049 ;
    END
  END VDD
  PIN VSS
    DIRECTION INOUT ;
    USE GROUND ;
    PORT
      LAYER M5 ;
        RECT  51 2.137 51.12 41.063 ;
        RECT  45.6 2.137 45.72 41.063 ;
        RECT  40.2 2.137 40.32 41.063 ;
        RECT  34.8 2.137 34.92 41.063 ;
        RECT  29.4 2.137 29.52 41.063 ;
        RECT  24 2.137 24.12 41.063 ;
        RECT  18.6 2.137 18.72 41.063 ;
        RECT  13.2 2.137 13.32 41.063 ;
        RECT  7.8 2.137 7.92 41.063 ;
        RECT  2.4 2.137 2.52 41.063 ;
    END
  END VSS
  # OT_OBS_CLOSED layer=M5 d_um=1.536 added=73
  OBS
    LAYER RVTN ;
     RECT  2.16 2.16 51.84 2.295 ;
     RECT  2.16 2.565 51.84 2.835 ;
     RECT  2.16 3.105 51.84 3.375 ;
     RECT  2.16 3.645 51.84 3.915 ;
     RECT  2.16 4.185 51.84 4.455 ;
     RECT  2.16 4.725 51.84 4.995 ;
     RECT  2.16 5.265 51.84 5.535 ;
     RECT  2.16 5.805 51.84 6.075 ;
     RECT  2.16 6.345 51.84 6.615 ;
     RECT  2.16 6.885 51.84 7.155 ;
     RECT  2.16 7.425 51.84 7.695 ;
     RECT  2.16 7.965 51.84 8.235 ;
     RECT  2.16 8.505 51.84 8.775 ;
     RECT  2.16 9.045 51.84 9.315 ;
     RECT  2.16 9.585 51.84 9.855 ;
     RECT  2.16 10.125 51.84 10.395 ;
     RECT  2.16 10.665 51.84 10.935 ;
     RECT  2.16 11.205 51.84 11.475 ;
     RECT  2.16 11.745 51.84 12.015 ;
     RECT  2.16 12.285 51.84 12.555 ;
     RECT  2.16 12.825 51.84 13.095 ;
     RECT  2.16 13.365 51.84 13.635 ;
     RECT  2.16 13.905 51.84 14.175 ;
     RECT  2.16 14.445 51.84 14.715 ;
     RECT  2.16 14.985 51.84 15.255 ;
     RECT  2.16 15.525 51.84 15.795 ;
     RECT  2.16 16.065 51.84 16.335 ;
     RECT  2.16 16.605 51.84 16.875 ;
     RECT  2.16 17.145 51.84 17.415 ;
     RECT  2.16 17.685 51.84 17.955 ;
     RECT  2.16 18.225 51.84 18.495 ;
     RECT  2.16 18.765 51.84 19.035 ;
     RECT  2.16 19.305 51.84 19.575 ;
     RECT  2.16 19.845 51.84 20.115 ;
     RECT  2.16 20.385 51.84 20.655 ;
     RECT  2.16 20.925 51.84 21.195 ;
     RECT  2.16 21.465 51.84 21.735 ;
     RECT  2.16 22.005 51.84 22.275 ;
     RECT  2.16 22.545 51.84 22.815 ;
     RECT  2.16 23.085 51.84 23.355 ;
     RECT  2.16 23.625 51.84 23.895 ;
     RECT  2.16 24.165 51.84 24.435 ;
     RECT  2.16 24.705 51.84 24.975 ;
     RECT  2.16 25.245 51.84 25.515 ;
     RECT  2.16 25.785 51.84 26.055 ;
     RECT  2.16 26.325 51.84 26.595 ;
     RECT  2.16 26.865 51.84 27.135 ;
     RECT  2.16 27.405 51.84 27.675 ;
     RECT  2.16 27.945 51.84 28.215 ;
     RECT  2.16 28.485 51.84 28.755 ;
     RECT  2.16 29.025 51.84 29.295 ;
     RECT  2.16 29.565 51.84 29.835 ;
     RECT  2.16 30.105 51.84 30.375 ;
     RECT  2.16 30.645 51.84 30.915 ;
     RECT  2.16 31.185 51.84 31.455 ;
     RECT  2.16 31.725 51.84 31.995 ;
     RECT  2.16 32.265 51.84 32.535 ;
     RECT  2.16 32.805 51.84 33.075 ;
     RECT  2.16 33.345 51.84 33.615 ;
     RECT  2.16 33.885 51.84 34.155 ;
     RECT  2.16 34.425 51.84 34.695 ;
     RECT  2.16 34.965 51.84 35.235 ;
     RECT  2.16 35.505 51.84 35.775 ;
     RECT  2.16 36.045 51.84 36.315 ;
     RECT  2.16 36.585 51.84 36.855 ;
     RECT  2.16 37.125 51.84 37.395 ;
     RECT  2.16 37.665 51.84 37.935 ;
     RECT  2.16 38.205 51.84 38.475 ;
     RECT  2.16 38.745 51.84 39.015 ;
     RECT  2.16 39.285 51.84 39.555 ;
     RECT  2.16 39.825 51.84 40.095 ;
     RECT  2.16 40.365 51.84 40.635 ;
     RECT  2.16 40.905 51.84 41.04 ;
    LAYER RVTP ;
     RECT  2.16 2.295 51.84 2.565 ;
     RECT  2.16 2.835 51.84 3.105 ;
     RECT  2.16 3.375 51.84 3.645 ;
     RECT  2.16 3.915 51.84 4.185 ;
     RECT  2.16 4.455 51.84 4.725 ;
     RECT  2.16 4.995 51.84 5.265 ;
     RECT  2.16 5.535 51.84 5.805 ;
     RECT  2.16 6.075 51.84 6.345 ;
     RECT  2.16 6.615 51.84 6.885 ;
     RECT  2.16 7.155 51.84 7.425 ;
     RECT  2.16 7.695 51.84 7.965 ;
     RECT  2.16 8.235 51.84 8.505 ;
     RECT  2.16 8.775 51.84 9.045 ;
     RECT  2.16 9.315 51.84 9.585 ;
     RECT  2.16 9.855 51.84 10.125 ;
     RECT  2.16 10.395 51.84 10.665 ;
     RECT  2.16 10.935 51.84 11.205 ;
     RECT  2.16 11.475 51.84 11.745 ;
     RECT  2.16 12.015 51.84 12.285 ;
     RECT  2.16 12.555 51.84 12.825 ;
     RECT  2.16 13.095 51.84 13.365 ;
     RECT  2.16 13.635 51.84 13.905 ;
     RECT  2.16 14.175 51.84 14.445 ;
     RECT  2.16 14.715 51.84 14.985 ;
     RECT  2.16 15.255 51.84 15.525 ;
     RECT  2.16 15.795 51.84 16.065 ;
     RECT  2.16 16.335 51.84 16.605 ;
     RECT  2.16 16.875 51.84 17.145 ;
     RECT  2.16 17.415 51.84 17.685 ;
     RECT  2.16 17.955 51.84 18.225 ;
     RECT  2.16 18.495 51.84 18.765 ;
     RECT  2.16 19.035 51.84 19.305 ;
     RECT  2.16 19.575 51.84 19.845 ;
     RECT  2.16 20.115 51.84 20.385 ;
     RECT  2.16 20.655 51.84 20.925 ;
     RECT  2.16 21.195 51.84 21.465 ;
     RECT  2.16 21.735 51.84 22.005 ;
     RECT  2.16 22.275 51.84 22.545 ;
     RECT  2.16 22.815 51.84 23.085 ;
     RECT  2.16 23.355 51.84 23.625 ;
     RECT  2.16 23.895 51.84 24.165 ;
     RECT  2.16 24.435 51.84 24.705 ;
     RECT  2.16 24.975 51.84 25.245 ;
     RECT  2.16 25.515 51.84 25.785 ;
     RECT  2.16 26.055 51.84 26.325 ;
     RECT  2.16 26.595 51.84 26.865 ;
     RECT  2.16 27.135 51.84 27.405 ;
     RECT  2.16 27.675 51.84 27.945 ;
     RECT  2.16 28.215 51.84 28.485 ;
     RECT  2.16 28.755 51.84 29.025 ;
     RECT  2.16 29.295 51.84 29.565 ;
     RECT  2.16 29.835 51.84 30.105 ;
     RECT  2.16 30.375 51.84 30.645 ;
     RECT  2.16 30.915 51.84 31.185 ;
     RECT  2.16 31.455 51.84 31.725 ;
     RECT  2.16 31.995 51.84 32.265 ;
     RECT  2.16 32.535 51.84 32.805 ;
     RECT  2.16 33.075 51.84 33.345 ;
     RECT  2.16 33.615 51.84 33.885 ;
     RECT  2.16 34.155 51.84 34.425 ;
     RECT  2.16 34.695 51.84 34.965 ;
     RECT  2.16 35.235 51.84 35.505 ;
     RECT  2.16 35.775 51.84 36.045 ;
     RECT  2.16 36.315 51.84 36.585 ;
     RECT  2.16 36.855 51.84 37.125 ;
     RECT  2.16 37.395 51.84 37.665 ;
     RECT  2.16 37.935 51.84 38.205 ;
     RECT  2.16 38.475 51.84 38.745 ;
     RECT  2.16 39.015 51.84 39.285 ;
     RECT  2.16 39.555 51.84 39.825 ;
     RECT  2.16 40.095 51.84 40.365 ;
     RECT  2.16 40.635 51.84 40.905 ;
    LAYER M1 ;
     RECT  2.16 2.151 51.84 41.049 ;
    LAYER M2 ;
     RECT  2.16 2.151 15.943 41.049 ;
     RECT  15.943 2.106 17.447 41.049 ;
     RECT  17.447 2.151 20.479 41.049 ;
     RECT  20.479 2.106 20.795 41.049 ;
     RECT  20.795 2.151 25.051 41.049 ;
     RECT  25.051 2.106 25.871 41.049 ;
     RECT  25.871 2.151 27.823 41.049 ;
     RECT  27.823 2.106 28.355 41.049 ;
     RECT  28.355 2.151 29.659 41.049 ;
     RECT  29.659 2.106 31.811 41.049 ;
     RECT  31.811 2.151 32.791 41.049 ;
     RECT  32.791 2.034 33.503 41.049 ;
     RECT  33.503 2.106 35.699 41.049 ;
     RECT  35.699 2.151 37.003 41.049 ;
     RECT  37.003 2.106 37.319 41.049 ;
     RECT  37.319 2.151 38.263 41.049 ;
     RECT  38.263 2.106 38.867 41.049 ;
     RECT  38.867 2.151 39.955 41.049 ;
     RECT  39.955 2.106 40.451 41.049 ;
     RECT  40.451 2.151 51.84 41.049 ;
     RECT  51.84 11.952 51.863 39.312 ;
     RECT  51.863 11.952 51.935 13.626 ;
     RECT  51.863 14.49 52.403 39.312 ;
     RECT  52.403 14.49 52.439 24.696 ;
     RECT  52.403 25.488 52.439 38.196 ;
     RECT  52.403 39.06 52.439 39.312 ;
     RECT  51.935 11.952 52.475 11.97 ;
     RECT  52.439 25.722 52.727 38.196 ;
     RECT  52.727 25.722 52.835 35.226 ;
     RECT  52.835 25.722 52.943 32.796 ;
     RECT  51.935 12.87 52.979 13.626 ;
     RECT  52.439 17.388 52.979 19.638 ;
     RECT  52.439 20.43 52.979 24.696 ;
     RECT  52.943 25.722 52.979 32.256 ;
     RECT  52.835 33.588 52.979 35.226 ;
     RECT  52.727 36.288 52.979 38.196 ;
     RECT  52.979 17.928 53.015 19.638 ;
     RECT  52.979 20.43 53.015 24.426 ;
     RECT  52.979 25.722 53.015 25.74 ;
     RECT  52.979 26.64 53.015 28.206 ;
     RECT  52.979 29.34 53.015 32.256 ;
     RECT  52.979 33.696 53.015 35.226 ;
     RECT  52.979 12.87 53.051 12.888 ;
     RECT  53.015 18.198 53.051 18.216 ;
     RECT  53.015 20.43 53.051 20.448 ;
     RECT  53.015 21.51 53.051 23.724 ;
     RECT  53.015 26.64 53.051 26.694 ;
     RECT  53.015 29.34 53.051 30.366 ;
     RECT  53.015 31.464 53.051 32.256 ;
     RECT  53.015 33.696 53.051 34.794 ;
     RECT  52.979 36.864 53.051 38.034 ;
     RECT  52.439 15.228 53.087 16.596 ;
     RECT  53.015 27.882 53.087 28.206 ;
     RECT  53.087 15.228 53.123 15.786 ;
     RECT  53.051 26.676 53.123 26.694 ;
     RECT  53.051 31.5 53.123 32.256 ;
     RECT  53.123 31.698 53.699 32.256 ;
     RECT  53.087 28.026 53.815 28.206 ;
     RECT  53.051 30.348 53.843 30.366 ;
     RECT  53.699 31.698 53.843 31.824 ;
     RECT  53.051 33.858 53.843 34.794 ;
     RECT  52.439 39.294 53.843 39.312 ;
     RECT  53.815 27.486 53.879 28.206 ;
     RECT  53.843 34.164 53.879 34.794 ;
     RECT  53.051 38.016 53.879 38.034 ;
     RECT  53.051 37.098 53.887 37.224 ;
     RECT  53.123 15.768 53.915 15.786 ;
     RECT  53.087 16.578 53.915 16.596 ;
     RECT  53.015 19.62 53.915 19.638 ;
     RECT  53.051 21.51 53.915 21.528 ;
     RECT  53.051 22.356 53.915 22.608 ;
     RECT  53.051 23.706 53.915 23.724 ;
     RECT  53.879 27.486 53.915 28.044 ;
     RECT  53.843 31.806 53.915 31.824 ;
     RECT  53.879 34.164 53.915 34.182 ;
     RECT  53.887 37.098 53.915 37.62 ;
     RECT  51.84 40.14 53.915 40.356 ;
     RECT  53.915 37.602 53.987 37.62 ;
     RECT  53.915 40.14 53.987 40.158 ;
    LAYER M3 ;
     RECT  16.236 0.091 16.866 0.139 ;
     RECT  15.624 0.139 16.866 0.523 ;
     RECT  18.36 0.091 18.774 0.523 ;
     RECT  19.908 0.091 19.926 0.523 ;
     RECT  36.18 0.091 36.198 0.523 ;
     RECT  24.444 0.139 24.462 0.571 ;
     RECT  25.596 0.091 25.614 0.571 ;
     RECT  29.268 0.091 29.286 0.571 ;
     RECT  34.956 0.571 34.974 0.619 ;
     RECT  19.908 0.523 20.07 1.099 ;
     RECT  27.756 0.571 27.774 1.099 ;
     RECT  29.268 0.571 29.394 1.099 ;
     RECT  22.248 0.571 23.238 1.147 ;
     RECT  24.408 0.571 24.786 1.147 ;
     RECT  25.596 0.571 26.514 1.147 ;
     RECT  29.196 1.099 29.394 1.147 ;
     RECT  30.492 0.091 31.122 1.147 ;
     RECT  33.084 0.091 33.102 1.147 ;
     RECT  34.02 0.091 34.038 1.147 ;
     RECT  34.956 0.619 35.226 1.147 ;
     RECT  15.624 0.523 17.154 1.675 ;
     RECT  18 0.523 18.774 1.675 ;
     RECT  27.756 1.099 28.278 1.675 ;
     RECT  39.312 0.091 39.618 1.675 ;
     RECT  15.624 1.675 18.774 1.723 ;
     RECT  19.908 1.099 20.898 1.723 ;
     RECT  22.248 1.147 26.514 1.723 ;
     RECT  27.756 1.675 28.314 1.723 ;
     RECT  29.196 1.147 31.23 1.723 ;
     RECT  32.292 1.147 32.31 1.723 ;
     RECT  33.084 1.147 35.226 1.723 ;
     RECT  36.18 0.523 36.63 1.723 ;
     RECT  37.8 0.571 37.818 1.723 ;
     RECT  39.204 1.675 39.618 1.723 ;
     RECT  19.908 1.723 31.23 2.101 ;
     RECT  32.148 1.723 40.374 2.101 ;
     RECT  15.624 1.723 19.134 2.263 ;
     RECT  19.908 2.101 40.446 2.263 ;
     RECT  2.415 2.143 2.505 2.413 ;
     RECT  7.815 2.143 7.905 2.413 ;
     RECT  13.215 2.143 13.305 2.413 ;
     RECT  15.624 2.263 40.446 2.413 ;
     RECT  45.615 2.143 45.705 2.413 ;
     RECT  51.015 2.143 51.105 2.413 ;
     RECT  15.624 2.413 40.497 2.605 ;
     RECT  15.552 2.605 40.554 2.641 ;
     RECT  15.552 2.641 40.734 2.911 ;
     RECT  15.336 2.911 40.734 3.181 ;
     RECT  15.336 3.181 41.166 3.299 ;
     RECT  15.588 3.299 41.166 4.109 ;
     RECT  15.696 4.109 41.166 4.261 ;
     RECT  15.696 4.261 41.598 4.649 ;
     RECT  15.876 4.649 41.598 5.575 ;
     RECT  15.588 5.575 41.598 6.449 ;
     RECT  15.624 6.449 41.598 7.579 ;
     RECT  15.552 7.579 41.598 7.619 ;
     RECT  15.624 7.619 41.598 8.699 ;
     RECT  16.56 8.699 41.598 11.209 ;
     RECT  45.615 2.413 45.897 11.713 ;
     RECT  43.344 11.281 43.362 11.785 ;
     RECT  43.056 11.785 43.362 12.019 ;
     RECT  16.56 11.209 41.922 12.091 ;
     RECT  42.66 12.019 43.362 12.091 ;
     RECT  51.015 2.413 51.297 12.181 ;
     RECT  50.652 12.181 51.297 12.217 ;
     RECT  52.452 11.947 52.47 12.217 ;
     RECT  50.652 12.217 52.47 12.325 ;
     RECT  44.964 11.713 45.897 12.361 ;
     RECT  44.892 12.361 45.897 12.451 ;
     RECT  16.56 12.091 43.362 12.479 ;
     RECT  47.196 12.289 47.214 12.631 ;
     RECT  44.388 12.451 45.897 12.757 ;
     RECT  46.764 12.631 47.214 12.793 ;
     RECT  50.004 12.325 52.47 12.829 ;
     RECT  49.536 12.829 52.47 12.865 ;
     RECT  44.208 12.757 45.897 12.901 ;
     RECT  46.656 12.793 47.214 12.901 ;
     RECT  48.78 12.361 48.798 12.901 ;
     RECT  49.536 12.865 53.046 12.901 ;
     RECT  43.128 12.479 43.362 12.929 ;
     RECT  47.988 12.487 48.006 12.991 ;
     RECT  48.78 12.901 53.046 12.991 ;
     RECT  16.56 12.479 42.354 13.019 ;
     RECT  44.208 12.901 47.214 13.019 ;
     RECT  47.988 12.991 53.046 13.037 ;
     RECT  44.46 13.019 47.214 13.063 ;
     RECT  47.988 13.037 51.966 13.063 ;
     RECT  52.956 13.037 53.046 13.133 ;
     RECT  16.56 13.019 42.21 13.289 ;
     RECT  44.46 13.063 51.966 13.397 ;
     RECT  43.128 12.929 43.326 13.405 ;
     RECT  45.504 13.397 51.966 13.433 ;
     RECT  45.504 13.433 46.098 13.469 ;
     RECT  16.56 13.289 41.526 13.559 ;
     RECT  46.98 13.433 51.966 13.559 ;
     RECT  52.956 13.133 52.974 13.631 ;
     RECT  43.02 13.405 43.326 13.667 ;
     RECT  45.576 13.469 46.098 13.667 ;
     RECT  43.02 13.667 43.146 13.739 ;
     RECT  47.196 13.559 51.966 13.771 ;
     RECT  44.46 13.397 44.478 13.829 ;
     RECT  45.615 13.667 46.098 13.901 ;
     RECT  16.56 13.559 41.454 13.973 ;
     RECT  16.56 13.973 41.418 14.099 ;
     RECT  45.615 13.901 45.954 14.099 ;
     RECT  47.196 13.771 52.434 14.099 ;
     RECT  47.196 14.099 49.914 14.207 ;
     RECT  50.688 14.099 52.434 14.207 ;
     RECT  41.292 14.099 41.418 14.369 ;
     RECT  50.688 14.207 51.534 14.369 ;
     RECT  41.292 14.369 41.31 14.405 ;
     RECT  52.416 14.207 52.434 14.513 ;
     RECT  47.196 14.207 47.502 14.953 ;
     RECT  15.624 8.699 15.75 15.089 ;
     RECT  48.492 14.207 49.914 15.295 ;
     RECT  50.688 14.369 51.297 15.295 ;
     RECT  53.1 15.223 53.118 15.295 ;
     RECT  48.492 15.295 51.297 15.331 ;
     RECT  45.615 14.099 45.897 15.421 ;
     RECT  48.348 15.331 51.297 15.421 ;
     RECT  15.624 15.089 15.714 15.449 ;
     RECT  47.052 14.953 47.502 15.643 ;
     RECT  48.348 15.421 51.354 15.643 ;
     RECT  45.615 15.421 45.954 15.763 ;
     RECT  47.052 15.643 51.354 15.799 ;
     RECT  52.452 15.295 53.118 15.799 ;
     RECT  45.615 15.763 46.026 15.979 ;
     RECT  45.072 15.979 46.026 16.025 ;
     RECT  15.696 15.449 15.714 16.061 ;
     RECT  43.02 13.739 43.038 16.069 ;
     RECT  42.768 16.069 43.038 16.331 ;
     RECT  47.052 15.799 53.118 16.411 ;
     RECT  16.56 14.099 40.497 16.439 ;
     RECT  45.615 16.025 46.026 16.507 ;
     RECT  46.872 16.411 53.118 16.507 ;
     RECT  16.992 16.439 40.497 16.529 ;
     RECT  42.804 16.331 43.038 16.555 ;
     RECT  42.804 16.555 43.11 16.651 ;
     RECT  42.804 16.651 43.146 16.709 ;
     RECT  16.992 16.529 17.226 16.799 ;
     RECT  45.615 16.507 53.118 17.165 ;
     RECT  18.036 16.529 40.497 17.213 ;
     RECT  16.992 16.799 17.01 17.339 ;
     RECT  45.615 17.165 53.046 17.455 ;
     RECT  18.108 17.213 40.497 17.519 ;
     RECT  53.892 15.763 53.91 17.549 ;
     RECT  42.804 16.709 43.038 17.645 ;
     RECT  44.352 17.455 53.046 17.645 ;
     RECT  18.216 17.519 40.497 17.681 ;
     RECT  44.352 17.645 45.99 17.681 ;
     RECT  18.396 17.681 40.497 18.221 ;
     RECT  46.872 17.645 53.046 18.317 ;
     RECT  42.768 17.923 42.786 18.563 ;
     RECT  44.64 17.681 45.99 18.661 ;
     RECT  46.872 18.317 53.01 18.661 ;
     RECT  18.615 18.221 40.497 18.869 ;
     RECT  44.64 18.661 53.01 19.103 ;
     RECT  18.615 18.869 18.954 19.229 ;
     RECT  42.804 19.075 42.822 19.229 ;
     RECT  7.815 2.413 8.097 19.345 ;
     RECT  19.728 18.869 40.497 19.381 ;
     RECT  42.732 19.507 42.75 19.643 ;
     RECT  44.64 19.103 52.398 19.679 ;
     RECT  44.64 19.679 51.642 19.963 ;
     RECT  44.532 19.963 51.642 20.011 ;
     RECT  52.416 20.011 52.434 20.107 ;
     RECT  44.496 20.011 51.642 20.155 ;
     RECT  19.728 19.381 41.094 20.191 ;
     RECT  41.832 20.011 41.85 20.191 ;
     RECT  42.804 20.047 42.894 20.219 ;
     RECT  52.416 20.107 52.938 20.299 ;
     RECT  44.46 20.155 51.642 20.347 ;
     RECT  19.728 20.191 41.85 20.389 ;
     RECT  52.416 20.299 52.974 20.417 ;
     RECT  52.884 20.417 52.974 20.425 ;
     RECT  2.415 2.413 2.697 20.461 ;
     RECT  7.704 19.345 8.097 20.477 ;
     RECT  2.304 20.461 2.697 20.525 ;
     RECT  52.884 20.425 53.046 20.525 ;
     RECT  19.728 20.389 41.958 20.623 ;
     RECT  44.316 20.347 51.642 20.683 ;
     RECT  44.316 20.683 51.894 21.127 ;
     RECT  19.728 20.623 42.678 21.235 ;
     RECT  44.028 21.127 51.894 21.245 ;
     RECT  44.892 21.245 51.894 21.271 ;
     RECT  52.884 20.525 53.01 21.271 ;
     RECT  19.728 21.235 42.822 21.389 ;
     RECT  53.892 19.615 53.91 21.533 ;
     RECT  44.028 21.245 44.046 21.659 ;
     RECT  34.092 21.389 42.822 21.667 ;
     RECT  34.092 21.667 43.11 21.803 ;
     RECT  44.892 21.271 53.01 21.811 ;
     RECT  44.892 21.811 53.046 22.073 ;
     RECT  52.92 22.073 53.046 22.157 ;
     RECT  34.092 21.803 43.074 22.199 ;
     RECT  44.892 22.073 51.93 22.207 ;
     RECT  34.092 22.199 42.786 22.235 ;
     RECT  52.92 22.157 53.01 22.235 ;
     RECT  19.728 21.389 33.282 22.267 ;
     RECT  44.712 22.207 51.93 22.459 ;
     RECT  19.728 22.267 33.426 22.469 ;
     RECT  34.56 22.235 42.786 22.469 ;
     RECT  34.56 22.469 40.497 22.493 ;
     RECT  41.22 22.469 42.786 22.505 ;
     RECT  44.568 22.459 51.93 22.505 ;
     RECT  42.408 22.505 42.786 22.541 ;
     RECT  34.776 22.493 40.497 22.577 ;
     RECT  41.22 22.505 41.454 22.739 ;
     RECT  41.22 22.739 41.238 22.775 ;
     RECT  42.66 22.541 42.786 22.775 ;
     RECT  44.964 22.505 51.93 22.781 ;
     RECT  52.92 22.235 52.974 23.083 ;
     RECT  42.768 22.775 42.786 23.089 ;
     RECT  45.036 22.781 51.93 23.089 ;
     RECT  52.92 23.083 53.01 23.089 ;
     RECT  42.768 23.089 42.858 23.125 ;
     RECT  45.036 23.089 53.01 23.323 ;
     RECT  19.728 22.469 33.282 23.359 ;
     RECT  42.768 23.125 43.362 23.395 ;
     RECT  19.728 23.359 33.318 23.459 ;
     RECT  42.768 23.395 43.434 23.585 ;
     RECT  45.036 23.323 53.046 23.611 ;
     RECT  19.728 23.459 31.878 23.729 ;
     RECT  53.892 22.315 53.91 23.729 ;
     RECT  42.768 23.585 42.966 23.891 ;
     RECT  44.892 23.611 53.046 24.269 ;
     RECT  35.892 22.577 40.497 24.283 ;
     RECT  34.776 22.577 35.097 24.325 ;
     RECT  27.72 23.729 31.878 24.359 ;
     RECT  34.704 24.325 35.097 24.365 ;
     RECT  35.892 24.283 41.022 24.367 ;
     RECT  42.768 23.891 42.93 24.461 ;
     RECT  35.892 24.367 41.094 24.467 ;
     RECT  42.768 24.461 42.894 24.475 ;
     RECT  28.692 24.359 31.878 24.629 ;
     RECT  42.588 24.475 42.894 24.665 ;
     RECT  27.72 24.359 27.81 24.701 ;
     RECT  44.892 24.269 53.01 24.749 ;
     RECT  28.98 24.629 31.878 24.899 ;
     RECT  29.016 24.899 31.518 25.007 ;
     RECT  19.728 23.729 26.91 25.169 ;
     RECT  29.016 25.007 31.194 25.169 ;
     RECT  42.732 24.665 42.894 25.249 ;
     RECT  44.892 24.749 52.974 25.291 ;
     RECT  44.712 25.291 52.974 25.325 ;
     RECT  29.016 25.169 31.158 25.439 ;
     RECT  34.776 24.365 35.097 25.475 ;
     RECT  42.732 25.249 43.506 25.591 ;
     RECT  29.415 25.439 31.158 25.709 ;
     RECT  45.615 25.325 52.974 25.717 ;
     RECT  45.615 25.717 53.01 25.771 ;
     RECT  42.228 25.591 43.506 25.825 ;
     RECT  35.892 24.467 40.497 25.963 ;
     RECT  35.892 25.963 40.95 25.979 ;
     RECT  45.615 25.771 53.046 25.979 ;
     RECT  36.036 25.979 40.95 26.023 ;
     RECT  42.192 25.825 43.506 26.023 ;
     RECT  44.712 25.325 44.73 26.023 ;
     RECT  36.036 26.023 43.506 26.293 ;
     RECT  36.036 26.293 43.65 26.393 ;
     RECT  36.036 26.393 40.497 26.519 ;
     RECT  44.46 26.023 44.73 26.635 ;
     RECT  52.272 25.979 53.046 26.671 ;
     RECT  44.46 26.635 44.874 26.761 ;
     RECT  45.615 25.979 51.534 26.761 ;
     RECT  52.272 26.671 53.118 26.765 ;
     RECT  37.08 26.519 40.497 26.789 ;
     RECT  44.46 26.761 51.534 26.789 ;
     RECT  45.18 26.789 51.534 26.827 ;
     RECT  52.272 26.765 53.01 26.827 ;
     RECT  41.472 26.393 43.65 26.869 ;
     RECT  37.116 26.789 40.497 27.059 ;
     RECT  41.472 26.869 44.298 27.059 ;
     RECT  41.544 27.059 44.298 27.095 ;
     RECT  37.116 27.059 37.782 27.329 ;
     RECT  42.084 27.095 44.298 27.389 ;
     RECT  45.18 26.827 53.01 27.473 ;
     RECT  53.82 27.451 53.838 27.481 ;
     RECT  36.036 26.519 36.342 27.571 ;
     RECT  42.12 27.389 44.298 27.571 ;
     RECT  45.18 27.473 51.39 27.571 ;
     RECT  37.548 27.329 37.782 27.599 ;
     RECT  42.12 27.571 51.39 27.599 ;
     RECT  52.344 27.473 53.01 27.629 ;
     RECT  42.192 27.599 51.39 27.716 ;
     RECT  52.38 27.629 53.01 27.787 ;
     RECT  53.82 27.481 53.91 27.787 ;
     RECT  34.815 25.475 35.097 27.841 ;
     RECT  36.036 27.571 36.738 27.841 ;
     RECT  38.592 27.059 40.497 27.913 ;
     RECT  52.38 27.787 53.91 27.917 ;
     RECT  42.228 27.716 51.39 27.941 ;
     RECT  53.856 27.917 53.91 28.049 ;
     RECT  52.38 27.917 53.082 28.205 ;
     RECT  53.856 28.049 53.874 28.211 ;
     RECT  42.372 27.941 51.39 28.283 ;
     RECT  38.592 27.913 41.058 28.291 ;
     RECT  43.668 28.283 51.39 28.291 ;
     RECT  38.484 28.291 41.058 28.319 ;
     RECT  38.484 28.319 40.986 28.409 ;
     RECT  43.668 28.291 51.498 28.493 ;
     RECT  19.728 25.169 26.838 28.589 ;
     RECT  34.056 28.453 34.074 28.651 ;
     RECT  34.815 27.841 36.738 28.651 ;
     RECT  19.728 28.589 24.462 28.679 ;
     RECT  38.628 28.409 40.497 28.679 ;
     RECT  42.372 28.283 42.93 28.679 ;
     RECT  43.848 28.493 51.498 28.747 ;
     RECT  52.38 28.205 53.046 28.747 ;
     RECT  38.628 28.679 38.862 28.751 ;
     RECT  43.848 28.747 53.046 28.823 ;
     RECT  42.372 28.679 42.894 28.949 ;
     RECT  44.244 28.823 53.046 28.985 ;
     RECT  38.736 28.751 38.754 29.057 ;
     RECT  32.76 23.459 33.282 29.065 ;
     RECT  34.056 28.651 36.738 29.065 ;
     RECT  44.28 28.985 53.046 29.129 ;
     RECT  44.28 29.129 51.498 29.219 ;
     RECT  42.768 28.949 42.894 29.291 ;
     RECT  42.768 29.291 42.858 29.399 ;
     RECT  20.124 28.679 24.462 29.489 ;
     RECT  42.84 29.399 42.858 29.489 ;
     RECT  32.76 29.065 36.738 29.597 ;
     RECT  52.344 29.129 53.046 29.741 ;
     RECT  20.664 29.489 24.462 29.831 ;
     RECT  52.344 29.741 53.01 29.831 ;
     RECT  34.632 29.597 36.738 29.839 ;
     RECT  34.632 29.839 36.81 29.875 ;
     RECT  25.236 28.589 26.838 29.939 ;
     RECT  32.76 29.597 33.822 30.029 ;
     RECT  45 29.219 51.498 30.109 ;
     RECT  52.344 29.831 52.974 30.109 ;
     RECT  38.664 29.911 38.682 30.137 ;
     RECT  34.632 29.875 36.954 30.173 ;
     RECT  45 30.109 52.974 30.271 ;
     RECT  44.64 30.271 52.974 30.317 ;
     RECT  34.632 30.173 36.882 30.343 ;
     RECT  42.768 30.271 42.786 30.343 ;
     RECT  20.916 29.831 24.462 30.443 ;
     RECT  20.916 30.443 21.402 30.479 ;
     RECT  44.64 30.317 51.606 30.569 ;
     RECT  44.712 30.569 51.426 30.605 ;
     RECT  52.344 30.317 52.974 30.667 ;
     RECT  42.768 30.343 42.93 30.713 ;
     RECT  42.768 30.713 42.858 30.749 ;
     RECT  44.856 30.605 51.426 30.749 ;
     RECT  52.344 30.667 53.01 30.794 ;
     RECT  20.916 30.479 20.934 30.839 ;
     RECT  34.596 30.343 36.882 30.839 ;
     RECT  34.704 30.839 36.882 30.845 ;
     RECT  52.38 30.794 53.01 30.955 ;
     RECT  52.38 30.955 53.046 31.051 ;
     RECT  25.236 29.939 26.766 31.081 ;
     RECT  25.236 31.081 26.802 31.153 ;
     RECT  52.38 31.051 53.082 31.243 ;
     RECT  53.82 29.419 53.838 31.243 ;
     RECT  25.236 31.153 26.874 31.289 ;
     RECT  22.644 30.443 24.462 31.379 ;
     RECT  45.504 30.749 51.426 31.495 ;
     RECT  38.736 31.423 38.754 31.523 ;
     RECT  45.324 31.495 51.426 31.531 ;
     RECT  34.776 30.845 36.882 31.559 ;
     RECT  45.324 31.531 51.642 31.565 ;
     RECT  42.768 30.749 42.822 31.627 ;
     RECT  23.04 31.379 24.462 31.649 ;
     RECT  25.236 31.289 26.73 31.757 ;
     RECT  42.768 31.627 42.93 31.757 ;
     RECT  52.38 31.243 53.838 31.801 ;
     RECT  25.236 31.757 26.658 31.829 ;
     RECT  52.38 31.801 53.91 31.853 ;
     RECT  34.815 31.559 36.882 31.955 ;
     RECT  45.615 31.565 51.642 32.011 ;
     RECT  52.38 31.853 53.694 32.011 ;
     RECT  23.04 31.649 24.297 32.189 ;
     RECT  45.615 32.011 53.694 32.261 ;
     RECT  42.768 31.757 42.786 32.369 ;
     RECT  44.712 32.155 44.874 32.827 ;
     RECT  45.615 32.261 52.974 32.827 ;
     RECT  34.815 31.955 35.097 32.965 ;
     RECT  34.704 32.965 35.097 33.005 ;
     RECT  25.236 31.829 26.514 33.179 ;
     RECT  44.712 32.827 52.974 33.413 ;
     RECT  44.712 33.413 51.426 33.611 ;
     RECT  44.856 33.611 51.426 33.629 ;
     RECT  53.82 33.451 53.838 33.643 ;
     RECT  52.38 33.413 52.974 33.691 ;
     RECT  52.38 33.691 53.046 33.773 ;
     RECT  53.82 33.643 53.874 33.881 ;
     RECT  23.58 32.189 24.297 33.917 ;
     RECT  53.856 33.881 53.874 33.931 ;
     RECT  36.252 31.955 36.882 33.953 ;
     RECT  25.704 33.179 26.514 33.989 ;
     RECT  45.036 33.629 51.426 34.115 ;
     RECT  53.856 33.931 53.91 34.187 ;
     RECT  45.288 34.115 51.426 34.205 ;
     RECT  42.768 33.787 42.786 34.231 ;
     RECT  36.864 33.953 36.882 34.259 ;
     RECT  45.615 34.205 51.426 34.393 ;
     RECT  52.38 33.773 53.01 34.393 ;
     RECT  42.768 34.231 42.822 34.429 ;
     RECT  26.064 33.989 26.514 34.457 ;
     RECT  34.815 33.005 35.097 34.591 ;
     RECT  34.704 34.591 35.097 34.637 ;
     RECT  53.856 34.187 53.874 34.799 ;
     RECT  45.615 34.393 53.01 34.925 ;
     RECT  26.496 34.457 26.514 35.069 ;
     RECT  42.768 34.429 42.858 35.069 ;
     RECT  52.344 34.925 53.01 35.179 ;
     RECT  27.72 24.701 27.738 35.231 ;
     RECT  42.84 35.069 42.858 35.231 ;
     RECT  45.615 34.925 51.462 35.659 ;
     RECT  52.344 35.179 53.046 35.659 ;
     RECT  44.712 35.899 44.73 35.941 ;
     RECT  44.712 35.941 44.874 35.969 ;
     RECT  30.492 25.709 31.158 36.149 ;
     RECT  44.856 35.969 44.874 36.419 ;
     RECT  30.924 36.149 31.158 36.509 ;
     RECT  42.768 36.481 42.786 36.689 ;
     RECT  53.892 35.563 53.91 37.099 ;
     RECT  31.14 36.509 31.158 37.193 ;
     RECT  45.615 35.659 53.046 37.427 ;
     RECT  53.856 37.099 53.91 37.597 ;
     RECT  45.615 37.427 53.01 37.625 ;
     RECT  32.76 30.029 33.282 37.733 ;
     RECT  32.76 37.733 33.246 37.769 ;
     RECT  46.98 37.625 47.214 37.859 ;
     RECT  48.06 37.625 52.974 37.859 ;
     RECT  45.615 37.625 46.206 38.045 ;
     RECT  53.856 37.597 53.982 38.059 ;
     RECT  48.132 37.859 52.974 38.201 ;
     RECT  32.76 37.769 32.994 38.309 ;
     RECT  47.196 37.859 47.214 38.371 ;
     RECT  32.76 38.309 32.922 38.579 ;
     RECT  47.196 38.371 47.358 38.587 ;
     RECT  46.764 38.587 47.358 38.717 ;
     RECT  48.132 38.201 52.434 38.779 ;
     RECT  47.808 38.779 52.434 38.939 ;
     RECT  48.456 38.939 52.434 39.083 ;
     RECT  48.456 39.083 51.75 39.317 ;
     RECT  53.82 38.059 53.982 39.317 ;
     RECT  32.904 38.579 32.922 39.389 ;
     RECT  48.744 39.317 51.75 39.515 ;
     RECT  49.068 39.515 51.75 39.749 ;
     RECT  49.068 39.749 51.642 39.785 ;
     RECT  49.068 39.785 51.297 39.917 ;
     RECT  49.608 39.917 51.297 40.019 ;
     RECT  53.892 39.317 53.982 40.163 ;
     RECT  53.892 40.163 53.91 40.361 ;
     RECT  49.608 40.019 49.626 40.469 ;
     RECT  50.724 40.019 51.297 40.559 ;
     RECT  2.415 20.525 2.697 40.787 ;
     RECT  7.815 20.477 8.097 40.787 ;
     RECT  13.215 2.413 13.497 40.787 ;
     RECT  18.615 19.229 18.897 40.787 ;
     RECT  24.015 33.917 24.297 40.787 ;
     RECT  29.415 25.709 29.697 40.787 ;
     RECT  34.815 34.637 35.097 40.787 ;
     RECT  40.215 28.679 40.497 40.787 ;
     RECT  45.615 38.045 45.897 40.787 ;
     RECT  51.015 40.559 51.297 40.787 ;
     RECT  2.415 40.787 2.505 41.057 ;
     RECT  7.815 40.787 7.905 41.057 ;
     RECT  13.215 40.787 13.305 41.057 ;
     RECT  18.615 40.787 18.705 41.057 ;
     RECT  24.015 40.787 24.105 41.057 ;
     RECT  29.415 40.787 29.505 41.057 ;
     RECT  34.815 40.787 34.905 41.057 ;
     RECT  40.215 40.787 40.305 41.057 ;
     RECT  45.615 40.787 45.705 41.057 ;
     RECT  51.015 40.787 51.105 41.057 ;
    LAYER M4 ;
     RECT  0.06 20.4 0.179 20.52 ;
     RECT  0.179 20.496 2.408 20.52 ;
     RECT  0.133 22.272 2.408 22.296 ;
     RECT  2.408 2.148 2.512 41.052 ;
     RECT  2.512 2.418 2.704 40.782 ;
     RECT  2.704 20.448 7.808 20.472 ;
     RECT  2.704 22.272 7.808 22.296 ;
     RECT  7.808 2.148 7.912 41.052 ;
     RECT  7.912 2.418 8.104 40.782 ;
     RECT  8.104 22.272 13.208 22.296 ;
     RECT  13.208 2.148 13.312 41.052 ;
     RECT  13.312 2.418 13.504 40.782 ;
     RECT  15.541 7.584 15.877 7.608 ;
     RECT  15.877 6.672 15.964 7.608 ;
     RECT  15.613 0.144 16.069 0.168 ;
     RECT  15.964 7.584 16.405 7.608 ;
     RECT  16.369 1.728 16.549 1.752 ;
     RECT  16.069 0.096 16.621 0.168 ;
     RECT  16.549 1.152 16.621 1.752 ;
     RECT  16.405 7.584 16.733 7.992 ;
     RECT  16.621 0.096 16.841 1.752 ;
     RECT  16.841 1.68 16.901 1.752 ;
     RECT  16.841 0.096 16.921 0.552 ;
     RECT  16.153 2.88 17.161 2.904 ;
     RECT  16.901 1.68 17.197 1.8 ;
     RECT  17.161 2.88 17.197 2.952 ;
     RECT  17.197 1.68 17.317 2.952 ;
     RECT  17.317 1.68 17.413 3.432 ;
     RECT  17.413 1.68 17.525 3.48 ;
     RECT  16.733 7.584 17.688 7.608 ;
     RECT  17.089 10.368 17.701 10.392 ;
     RECT  17.525 1.68 17.843 3.432 ;
     RECT  17.701 9.696 17.917 10.392 ;
     RECT  16.921 0.528 18.035 0.552 ;
     RECT  17.843 1.728 18.608 3.432 ;
     RECT  17.688 6.816 18.608 7.608 ;
     RECT  17.593 8.64 18.608 8.664 ;
     RECT  17.917 9.696 18.608 11.304 ;
     RECT  13.504 22.272 18.608 22.296 ;
     RECT  18.608 1.728 18.712 41.052 ;
     RECT  18.277 0.096 18.785 0.168 ;
     RECT  18.712 1.728 18.904 40.782 ;
     RECT  18.904 2.88 18.965 3.336 ;
     RECT  18.904 6.816 18.965 7.464 ;
     RECT  18.785 0.144 19.043 0.168 ;
     RECT  18.965 2.928 19.109 3.336 ;
     RECT  19.109 2.928 19.181 2.952 ;
     RECT  18.904 12.528 19.181 13.128 ;
     RECT  18.904 14.832 19.217 14.856 ;
     RECT  18.904 10.704 19.397 10.728 ;
     RECT  19.181 12.528 19.649 12.552 ;
     RECT  18.904 1.728 19.969 1.8 ;
     RECT  19.897 0.096 19.981 0.12 ;
     RECT  20.041 0.528 20.147 0.552 ;
     RECT  19.969 1.728 20.348 2.28 ;
     RECT  20.293 3.408 20.377 3.432 ;
     RECT  20.221 11.424 20.473 11.448 ;
     RECT  20.348 1.104 20.581 2.28 ;
     RECT  19.969 9.168 20.653 9.192 ;
     RECT  20.581 1.104 20.664 2.328 ;
     RECT  18.965 7.056 20.761 7.464 ;
     RECT  20.664 1.104 20.915 2.376 ;
     RECT  20.473 11.424 20.941 12.216 ;
     RECT  20.915 1.728 21.107 2.376 ;
     RECT  20.761 6.672 21.233 7.464 ;
     RECT  21.157 3.984 21.253 4.2 ;
     RECT  20.653 9.12 21.377 9.192 ;
     RECT  21.253 3.984 21.449 5.16 ;
     RECT  20.941 10.848 21.557 12.216 ;
     RECT  21.449 3.984 21.593 4.2 ;
     RECT  21.377 9.12 21.593 9.144 ;
     RECT  21.445 2.88 21.829 2.904 ;
     RECT  21.829 2.88 21.953 3.432 ;
     RECT  21.557 10.848 22.097 11.448 ;
     RECT  21.107 1.728 22.117 1.752 ;
     RECT  21.233 6.672 22.133 7.08 ;
     RECT  22.069 8.4 22.156 8.424 ;
     RECT  22.193 0.576 22.345 0.6 ;
     RECT  22.117 1.728 22.345 1.848 ;
     RECT  22.097 11.136 22.556 11.448 ;
     RECT  21.697 12.864 22.556 12.888 ;
     RECT  22.556 11.136 22.643 12.888 ;
     RECT  22.345 0.576 22.681 1.848 ;
     RECT  22.643 12.864 22.817 12.888 ;
     RECT  22.643 11.136 22.853 11.4 ;
     RECT  22.681 1.728 22.885 1.848 ;
     RECT  21.953 2.88 22.885 2.904 ;
     RECT  22.561 7.248 22.957 7.272 ;
     RECT  22.885 1.728 23.029 2.904 ;
     RECT  22.741 3.984 23.029 4.008 ;
     RECT  22.813 30.144 23.029 30.168 ;
     RECT  23.029 1.728 23.173 4.008 ;
     RECT  23.029 5.52 23.173 5.544 ;
     RECT  22.957 7.248 23.173 7.704 ;
     RECT  23.173 7.248 23.245 7.752 ;
     RECT  23.245 7.248 23.317 7.896 ;
     RECT  22.853 11.136 23.461 11.16 ;
     RECT  23.101 9.504 23.605 9.528 ;
     RECT  22.681 0.576 23.845 0.6 ;
     RECT  23.173 1.728 23.845 5.544 ;
     RECT  23.461 10.704 23.857 11.16 ;
     RECT  23.317 7.248 23.929 7.992 ;
     RECT  18.904 22.272 23.929 22.296 ;
     RECT  23.845 0.576 23.933 5.544 ;
     RECT  23.933 1.728 24.008 5.544 ;
     RECT  23.929 6.576 24.008 7.992 ;
     RECT  23.605 9.12 24.008 9.528 ;
     RECT  23.857 10.704 24.008 11.688 ;
     RECT  23.029 14.208 24.008 14.232 ;
     RECT  23.929 22.272 24.008 23.064 ;
     RECT  23.029 30.144 24.008 30.456 ;
     RECT  23.933 0.576 24.037 0.6 ;
     RECT  24.008 1.728 24.112 41.052 ;
     RECT  24.112 1.728 24.304 40.782 ;
     RECT  24.037 0.24 24.389 0.6 ;
     RECT  24.304 7.92 24.419 9.336 ;
     RECT  24.304 10.608 24.419 11.688 ;
     RECT  24.304 1.728 24.473 6.792 ;
     RECT  24.419 10.704 24.473 11.688 ;
     RECT  24.473 10.992 24.509 11.688 ;
     RECT  24.473 3.36 24.515 6.792 ;
     RECT  24.515 3.36 24.689 4.584 ;
     RECT  24.389 0.144 24.797 0.6 ;
     RECT  24.419 7.92 24.797 8.52 ;
     RECT  24.689 3.36 24.977 4.008 ;
     RECT  24.509 11.136 24.977 11.688 ;
     RECT  24.473 1.728 25.093 2.328 ;
     RECT  24.797 7.968 25.121 8.52 ;
     RECT  24.304 21.648 25.273 23.064 ;
     RECT  25.273 22.272 25.405 23.064 ;
     RECT  24.304 24.384 25.405 24.408 ;
     RECT  25.381 0.096 25.625 0.12 ;
     RECT  25.093 1.152 25.661 2.328 ;
     RECT  25.661 1.728 25.669 2.328 ;
     RECT  24.977 3.36 25.669 3.432 ;
     RECT  24.977 11.136 25.945 11.16 ;
     RECT  25.957 4.56 26.053 4.584 ;
     RECT  24.515 6.576 26.089 6.792 ;
     RECT  24.304 32.976 26.149 33.816 ;
     RECT  25.669 1.728 26.161 3.432 ;
     RECT  26.053 4.56 26.165 5.16 ;
     RECT  26.089 6.576 26.195 6.84 ;
     RECT  25.121 8.496 26.2 8.52 ;
     RECT  26.195 6.72 26.237 6.84 ;
     RECT  26.165 5.04 26.243 5.064 ;
     RECT  26.161 1.728 26.273 3.48 ;
     RECT  24.304 20.592 26.3 20.616 ;
     RECT  26.273 1.728 26.381 3.432 ;
     RECT  26.3 20.592 26.387 21.048 ;
     RECT  25.621 13.056 26.437 13.08 ;
     RECT  26.437 12.48 26.449 13.08 ;
     RECT  25.873 14.352 26.449 14.376 ;
     RECT  25.945 10.56 26.483 11.16 ;
     RECT  26.2 8.448 26.525 8.52 ;
     RECT  26.449 12.48 26.819 14.376 ;
     RECT  26.819 14.256 26.86 14.376 ;
     RECT  25.405 22.272 27.025 24.408 ;
     RECT  26.483 10.56 27.065 10.584 ;
     RECT  26.237 6.72 27.101 6.744 ;
     RECT  26.149 32.976 27.301 34.632 ;
     RECT  26.819 12.48 27.317 13.08 ;
     RECT  27.26 4.272 27.347 4.296 ;
     RECT  26.525 8.448 27.457 8.472 ;
     RECT  27.317 12.48 27.461 12.6 ;
     RECT  26.381 1.728 27.605 3 ;
     RECT  27.457 7.968 27.709 8.472 ;
     RECT  27.461 12.48 27.709 12.552 ;
     RECT  27.709 7.344 27.749 9.144 ;
     RECT  27.709 11.76 27.749 12.552 ;
     RECT  25.861 0.576 27.785 0.6 ;
     RECT  27.749 9.12 27.965 9.144 ;
     RECT  27.749 11.76 28.069 12.504 ;
     RECT  27.605 1.728 28.22 2.328 ;
     RECT  28.069 10.8 28.825 12.504 ;
     RECT  28.22 1.104 29.005 2.328 ;
     RECT  29.005 1.104 29.077 2.856 ;
     RECT  27.685 3.984 29.077 4.008 ;
     RECT  27.781 5.712 29.149 5.736 ;
     RECT  29.125 0.096 29.173 0.12 ;
     RECT  29.077 1.104 29.173 2.904 ;
     RECT  29.077 3.984 29.173 4.68 ;
     RECT  29.149 5.712 29.173 6.312 ;
     RECT  27.749 7.344 29.173 7.992 ;
     RECT  29.173 5.712 29.221 7.992 ;
     RECT  29.221 5.712 29.269 8.04 ;
     RECT  28.825 9.456 29.269 12.504 ;
     RECT  29.173 0.096 29.297 4.68 ;
     RECT  29.297 0.192 29.408 4.68 ;
     RECT  29.269 5.712 29.408 12.504 ;
     RECT  26.86 14.352 29.408 14.376 ;
     RECT  26.387 20.592 29.408 20.616 ;
     RECT  27.025 21.936 29.408 24.408 ;
     RECT  25.441 25.44 29.408 25.464 ;
     RECT  24.304 30.432 29.408 30.84 ;
     RECT  27.301 32.976 29.408 34.92 ;
     RECT  29.408 0.192 29.512 41.052 ;
     RECT  29.512 0.192 29.651 40.782 ;
     RECT  29.651 1.152 29.704 40.782 ;
     RECT  29.704 1.152 29.837 4.008 ;
     RECT  29.837 1.68 29.939 4.008 ;
     RECT  29.704 7.776 30.449 9.096 ;
     RECT  29.704 5.136 30.629 5.16 ;
     RECT  29.704 20.592 30.733 20.616 ;
     RECT  29.704 21.936 30.733 24.408 ;
     RECT  29.939 1.728 30.737 4.008 ;
     RECT  30.373 0.096 30.757 0.12 ;
     RECT  29.704 6.528 30.853 6.552 ;
     RECT  29.704 11.136 30.913 11.16 ;
     RECT  30.757 0.096 30.949 0.312 ;
     RECT  30.737 2.304 30.985 4.008 ;
     RECT  30.949 0.096 30.995 1.176 ;
     RECT  30.853 5.712 30.997 6.552 ;
     RECT  30.449 7.776 30.997 8.856 ;
     RECT  29.704 13.824 31.025 14.856 ;
     RECT  30.995 0.096 31.133 0.12 ;
     RECT  30.913 10.224 31.169 11.16 ;
     RECT  30.733 20.592 31.345 24.408 ;
     RECT  29.704 25.44 31.345 25.464 ;
     RECT  29.704 12.528 31.381 12.552 ;
     RECT  31.057 16.512 31.381 16.536 ;
     RECT  30.985 2.304 31.385 4.536 ;
     RECT  30.997 5.712 31.457 8.856 ;
     RECT  31.381 15.984 31.465 16.536 ;
     RECT  31.381 12.528 31.619 12.792 ;
     RECT  31.457 8.832 31.669 8.856 ;
     RECT  31.169 10.224 31.669 11.064 ;
     RECT  31.669 8.832 31.853 11.064 ;
     RECT  31.877 4.56 31.961 4.584 ;
     RECT  31.457 5.712 31.961 7.848 ;
     RECT  30.995 1.152 32.093 1.176 ;
     RECT  31.385 2.304 32.093 3.528 ;
     RECT  31.961 5.712 32.245 7.08 ;
     RECT  31.345 20.592 32.317 25.464 ;
     RECT  32.093 1.152 32.321 3.528 ;
     RECT  32.321 1.728 32.429 3.528 ;
     RECT  31.853 8.832 32.497 9.72 ;
     RECT  32.429 1.728 32.531 3 ;
     RECT  32.245 5.472 32.537 7.08 ;
     RECT  31.465 16.512 32.569 16.536 ;
     RECT  32.485 3.984 32.681 4.056 ;
     RECT  32.497 8.496 32.753 9.72 ;
     RECT  31.853 11.04 32.785 11.064 ;
     RECT  32.531 1.728 32.789 2.904 ;
     RECT  32.785 11.04 32.857 11.208 ;
     RECT  32.789 1.728 32.969 2.28 ;
     RECT  32.753 8.496 33.001 9.576 ;
     RECT  33.001 8.4 33.037 9.576 ;
     RECT  32.681 4.032 33.073 4.056 ;
     RECT  32.857 10.848 33.077 11.448 ;
     RECT  32.537 6.24 33.149 7.08 ;
     RECT  33.149 6.24 33.185 6.888 ;
     RECT  32.569 16.512 33.217 17.4 ;
     RECT  33.037 8.304 33.325 9.576 ;
     RECT  33.077 11.424 33.433 11.448 ;
     RECT  31.619 12.72 33.433 12.792 ;
     RECT  33.325 7.872 33.653 9.576 ;
     RECT  32.969 1.728 33.713 2.184 ;
     RECT  33.073 4.032 33.833 5.112 ;
     RECT  33.833 4.032 33.865 4.056 ;
     RECT  33.713 1.152 34.045 2.184 ;
     RECT  33.433 11.424 34.045 12.792 ;
     RECT  33.061 0.096 34.049 0.12 ;
     RECT  34.045 1.152 34.117 2.28 ;
     RECT  33.865 3.408 34.117 4.056 ;
     RECT  33.185 6.864 34.261 6.888 ;
     RECT  34.261 6.48 34.405 6.888 ;
     RECT  33.653 7.872 34.405 9.336 ;
     RECT  34.405 6.48 34.549 9.336 ;
     RECT  34.117 1.152 34.625 4.056 ;
     RECT  34.625 1.728 34.808 4.056 ;
     RECT  33.833 5.088 34.808 5.112 ;
     RECT  34.549 6.288 34.808 9.336 ;
     RECT  34.045 10.848 34.808 12.792 ;
     RECT  31.025 13.824 34.808 14.376 ;
     RECT  33.217 16.32 34.808 17.4 ;
     RECT  32.317 20.4 34.808 25.464 ;
     RECT  29.704 30.432 34.808 30.84 ;
     RECT  29.704 32.976 34.808 34.92 ;
     RECT  34.808 1.728 34.912 41.052 ;
     RECT  34.789 0.576 34.985 0.648 ;
     RECT  34.912 1.728 35.104 40.782 ;
     RECT  34.985 0.624 35.237 0.648 ;
     RECT  35.104 8.544 35.245 9.768 ;
     RECT  35.104 10.896 35.273 14.808 ;
     RECT  35.273 11.28 35.281 14.808 ;
     RECT  35.281 11.28 35.308 14.712 ;
     RECT  35.245 9.648 35.345 9.768 ;
     RECT  35.245 8.544 35.381 8.568 ;
     RECT  35.104 1.728 35.597 4.584 ;
     RECT  35.597 1.728 35.641 4.536 ;
     RECT  35.641 2.88 36.029 4.536 ;
     RECT  35.104 6.864 36.125 7.416 ;
     RECT  36.029 3.408 36.181 4.536 ;
     RECT  36.037 0.096 36.209 0.12 ;
     RECT  36.125 6.864 36.209 7.464 ;
     RECT  35.104 16.32 36.277 16.392 ;
     RECT  36.209 6.864 36.317 7.416 ;
     RECT  35.308 11.28 36.349 14.376 ;
     RECT  36.277 15.792 36.349 16.392 ;
     RECT  35.345 9.648 36.389 9.672 ;
     RECT  36.349 11.28 36.389 16.392 ;
     RECT  36.181 3.408 36.425 4.008 ;
     RECT  36.389 11.28 36.461 14.856 ;
     RECT  35.104 30.432 36.524 31.944 ;
     RECT  36.425 3.408 36.569 3.432 ;
     RECT  36.461 11.28 36.605 14.376 ;
     RECT  36.524 30.192 36.611 31.944 ;
     RECT  36.572 0.528 36.659 0.552 ;
     RECT  36.611 30.432 36.668 31.944 ;
     RECT  35.104 32.976 36.668 34.92 ;
     RECT  36.668 30.432 36.755 34.92 ;
     RECT  35.104 5.712 36.857 5.736 ;
     RECT  35.641 1.728 36.956 1.752 ;
     RECT  36.317 7.392 37.001 7.416 ;
     RECT  36.605 11.28 37.217 11.304 ;
     RECT  36.605 12.384 37.217 14.376 ;
     RECT  36.956 1.728 37.36 1.848 ;
     RECT  37.217 13.824 37.429 14.376 ;
     RECT  37.285 10.608 37.433 10.872 ;
     RECT  37.477 4.08 37.501 4.104 ;
     RECT  36.493 8.928 37.501 8.952 ;
     RECT  37.429 13.824 37.577 14.856 ;
     RECT  37.501 8.496 37.585 8.952 ;
     RECT  37.501 4.08 37.619 4.2 ;
     RECT  37.585 8.928 37.721 8.952 ;
     RECT  37.745 0.576 37.829 0.6 ;
     RECT  37.36 1.728 37.861 1.896 ;
     RECT  37.861 1.728 38.053 2.184 ;
     RECT  38.053 1.728 38.369 2.904 ;
     RECT  37.433 10.608 38.441 10.632 ;
     RECT  38.369 2.832 38.765 2.904 ;
     RECT  37.619 4.08 38.909 4.104 ;
     RECT  38.765 2.88 38.945 2.904 ;
     RECT  38.833 18.768 38.945 18.792 ;
     RECT  35.104 20.4 39.085 25.464 ;
     RECT  38.369 1.728 39.16 1.752 ;
     RECT  39.085 20.4 39.197 25.8 ;
     RECT  38.977 27.408 39.197 27.432 ;
     RECT  35.104 17.376 39.229 17.4 ;
     RECT  38.149 9.072 39.233 9.096 ;
     RECT  38.761 11.376 39.301 11.4 ;
     RECT  37.217 12.384 39.301 12.744 ;
     RECT  37.577 13.824 39.301 14.376 ;
     RECT  39.16 1.68 39.397 1.752 ;
     RECT  39.397 1.152 39.593 1.752 ;
     RECT  39.205 0.096 39.673 0.12 ;
     RECT  39.593 1.728 39.685 1.752 ;
     RECT  39.685 1.728 39.781 1.8 ;
     RECT  39.781 1.728 40.208 1.848 ;
     RECT  39.301 11.376 40.208 14.376 ;
     RECT  36.389 16.32 40.208 16.392 ;
     RECT  39.229 17.376 40.208 17.64 ;
     RECT  39.197 20.4 40.208 25.464 ;
     RECT  36.755 30.432 40.208 31.8 ;
     RECT  36.755 32.88 40.208 34.92 ;
     RECT  40.208 1.728 40.312 41.052 ;
     RECT  40.312 1.728 40.385 40.782 ;
     RECT  40.385 2.418 40.504 40.782 ;
     RECT  40.504 11.376 40.643 11.4 ;
     RECT  40.504 12.528 41.069 12.792 ;
     RECT  40.504 20.4 42.145 25.992 ;
     RECT  42.073 27.36 42.145 27.384 ;
     RECT  42.145 20.4 42.181 27.384 ;
     RECT  40.504 16.32 42.829 16.392 ;
     RECT  40.504 17.616 42.829 17.64 ;
     RECT  41.069 12.768 43.081 12.792 ;
     RECT  40.504 13.824 43.081 14.376 ;
     RECT  42.829 16.32 43.157 17.64 ;
     RECT  43.081 12.768 43.229 14.376 ;
     RECT  42.181 20.4 43.657 27.576 ;
     RECT  43.657 20.4 43.661 28.488 ;
     RECT  43.661 27.312 43.907 28.488 ;
     RECT  43.907 27.456 44.017 28.488 ;
     RECT  43.661 20.4 44.305 26.088 ;
     RECT  44.305 20.352 44.521 26.088 ;
     RECT  44.521 19.968 44.701 26.088 ;
     RECT  40.504 30.432 44.701 31.8 ;
     RECT  40.504 32.88 44.701 34.92 ;
     RECT  44.701 30.432 44.845 34.92 ;
     RECT  43.157 17.616 44.881 17.64 ;
     RECT  43.157 16.32 45.061 16.392 ;
     RECT  44.017 27.456 45.061 28.536 ;
     RECT  45.061 27.456 45.212 29.304 ;
     RECT  44.701 19.968 45.385 26.232 ;
     RECT  45.212 27.312 45.385 29.304 ;
     RECT  44.845 30.384 45.493 34.92 ;
     RECT  44.701 35.904 45.493 35.928 ;
     RECT  43.229 12.768 45.608 12.792 ;
     RECT  43.229 13.824 45.608 14.376 ;
     RECT  45.061 15.984 45.608 16.392 ;
     RECT  44.881 17.616 45.608 18.216 ;
     RECT  45.385 19.968 45.608 29.304 ;
     RECT  45.493 30.384 45.608 35.928 ;
     RECT  45.608 2.148 45.712 41.052 ;
     RECT  45.712 2.418 45.904 40.782 ;
     RECT  45.904 38.016 46.259 38.712 ;
     RECT  45.904 19.776 46.505 36.888 ;
     RECT  45.904 18.288 46.933 18.312 ;
     RECT  46.933 18.288 47.005 18.552 ;
     RECT  46.505 20.304 47.221 36.888 ;
     RECT  47.005 18 47.365 18.552 ;
     RECT  45.904 16.32 47.725 16.872 ;
     RECT  47.365 17.856 47.725 18.552 ;
     RECT  46.259 38.592 47.797 38.712 ;
     RECT  47.797 38.592 47.845 38.808 ;
     RECT  47.221 20.304 47.941 37.032 ;
     RECT  47.845 38.592 47.941 39.384 ;
     RECT  47.725 16.32 47.996 18.744 ;
     RECT  47.941 20.304 48.049 39.384 ;
     RECT  45.904 13.008 48.083 14.376 ;
     RECT  47.996 15.648 48.083 18.744 ;
     RECT  48.049 20.112 48.265 39.384 ;
     RECT  48.083 16.32 48.409 18.744 ;
     RECT  48.265 20.016 48.409 39.384 ;
     RECT  48.083 13.248 48.589 14.376 ;
     RECT  48.589 13.248 48.673 14.856 ;
     RECT  48.673 13.248 48.845 14.376 ;
     RECT  48.409 16.32 48.917 39.384 ;
     RECT  48.917 16.368 49.057 39.384 ;
     RECT  49.057 16.368 49.205 39.912 ;
     RECT  48.845 13.296 49.379 14.376 ;
     RECT  49.379 13.296 49.457 13.848 ;
     RECT  49.457 13.824 49.475 13.848 ;
     RECT  49.205 39.888 49.525 39.912 ;
     RECT  49.525 39.888 49.571 40.488 ;
     RECT  49.205 16.368 49.997 38.904 ;
     RECT  49.997 17.088 50.605 38.904 ;
     RECT  50.605 17.088 51.008 39.096 ;
     RECT  49.571 40.464 51.008 40.488 ;
     RECT  51.008 2.148 51.112 41.052 ;
     RECT  51.112 2.418 51.304 40.782 ;
     RECT  51.304 19.92 51.365 39.096 ;
     RECT  51.365 31.68 51.545 39.096 ;
     RECT  51.304 16.752 52.369 18.696 ;
     RECT  51.365 19.92 52.369 30.648 ;
     RECT  51.304 13.2 52.405 13.704 ;
     RECT  52.369 16.752 52.405 30.648 ;
     RECT  51.545 31.68 52.405 38.28 ;
     RECT  52.405 13.2 52.441 13.8 ;
     RECT  52.405 16.752 52.441 38.28 ;
     RECT  52.441 13.008 53.964 13.8 ;
     RECT  52.441 16.08 53.964 38.28 ;
    LAYER M5 ;
     RECT  16.08 0.016 40.008 0.131 ;
     RECT  16.176 0.131 40.008 0.179 ;
     RECT  16.272 0.179 40.008 1.763 ;
     RECT  16.272 1.763 19.08 1.811 ;
     RECT  39.696 1.763 40.008 1.811 ;
     RECT  20.208 1.763 38.184 1.859 ;
     RECT  39.792 1.811 40.008 1.859 ;
     RECT  2.4 2.137 2.52 2.151 ;
     RECT  7.8 2.137 7.92 2.151 ;
     RECT  13.2 2.137 13.32 2.151 ;
     RECT  40.2 2.137 40.32 2.151 ;
     RECT  45.6 2.137 45.72 2.151 ;
     RECT  51 2.137 51.12 2.151 ;
     RECT  20.208 1.859 38.088 2.195 ;
     RECT  20.208 2.195 32.904 2.291 ;
     RECT  16.272 1.811 19.032 2.915 ;
     RECT  20.304 2.291 32.904 2.915 ;
     RECT  34.032 2.195 38.088 2.915 ;
     RECT  17.328 2.915 19.032 2.963 ;
     RECT  25.968 2.915 32.904 3.011 ;
     RECT  18.48 2.963 18.912 3.107 ;
     RECT  17.328 2.963 17.448 3.443 ;
     RECT  20.304 2.915 21.864 3.443 ;
     RECT  25.968 3.011 26.28 3.443 ;
     RECT  34.032 2.915 37.608 3.443 ;
     RECT  17.424 3.443 17.448 3.491 ;
     RECT  21.168 3.443 21.384 4.019 ;
     RECT  23.04 2.915 24.936 4.019 ;
     RECT  27.696 3.011 32.904 4.067 ;
     RECT  34.176 3.443 37.608 4.211 ;
     RECT  27.696 4.067 31.944 4.261 ;
     RECT  25.968 3.443 26.232 4.595 ;
     RECT  27.312 4.261 31.944 4.595 ;
     RECT  26.064 4.595 26.232 5.075 ;
     RECT  21.264 4.019 21.288 5.171 ;
     RECT  26.064 5.075 26.184 5.171 ;
     RECT  27.312 4.595 31.8 5.171 ;
     RECT  23.04 4.019 24.504 5.555 ;
     RECT  27.312 5.171 29.712 5.747 ;
     RECT  30.864 5.171 31.8 5.747 ;
     RECT  34.176 4.211 36.84 5.747 ;
     RECT  23.328 5.555 24.504 6.611 ;
     RECT  26.16 5.171 26.184 6.611 ;
     RECT  18.6 3.107 18.912 6.805 ;
     RECT  29.184 5.747 29.712 6.851 ;
     RECT  34.176 5.747 36.168 6.899 ;
     RECT  31.008 5.747 31.8 6.947 ;
     RECT  21.12 6.661 21.144 7.045 ;
     RECT  21.12 7.045 22.104 7.475 ;
     RECT  36.144 6.899 36.168 7.475 ;
     RECT  15.888 6.661 15.912 7.619 ;
     RECT  17.76 6.805 18.912 7.619 ;
     RECT  23.328 6.611 24.312 8.003 ;
     RECT  29.232 6.851 29.712 8.051 ;
     RECT  27.312 5.747 27.336 8.485 ;
     RECT  29.28 8.051 29.712 8.579 ;
     RECT  34.176 6.899 35.112 8.869 ;
     RECT  23.616 8.003 24.312 9.155 ;
     RECT  31.536 6.947 31.8 9.155 ;
     RECT  24 9.155 24.312 9.301 ;
     RECT  34.176 8.869 35.208 9.779 ;
     RECT  31.536 9.155 31.56 10.307 ;
     RECT  24 9.301 24.408 10.643 ;
     RECT  18.6 7.619 18.912 10.693 ;
     RECT  34.176 9.779 35.112 10.931 ;
     RECT  18.24 10.693 18.912 11.315 ;
     RECT  22.08 7.475 22.104 11.365 ;
     RECT  40.2 2.151 40.512 11.365 ;
     RECT  22.08 11.365 22.632 11.459 ;
     RECT  22.608 11.459 22.632 12.227 ;
     RECT  37.536 8.485 37.56 12.373 ;
     RECT  37.056 12.373 37.56 12.419 ;
     RECT  26.448 8.485 27.336 12.515 ;
     RECT  31.584 10.789 31.608 12.517 ;
     RECT  31.392 12.517 31.608 12.563 ;
     RECT  39.312 11.365 40.632 12.563 ;
     RECT  26.784 12.515 27.336 12.611 ;
     RECT  45.6 2.151 45.912 12.757 ;
     RECT  37.056 12.419 37.08 12.803 ;
     RECT  39.312 12.563 40.512 13.139 ;
     RECT  24 10.643 24.312 14.197 ;
     RECT  48.048 12.997 48.072 14.197 ;
     RECT  49.44 13.813 49.464 14.197 ;
     RECT  26.784 12.611 26.808 14.291 ;
     RECT  34.8 10.931 35.112 14.677 ;
     RECT  34.8 14.677 35.256 14.819 ;
     RECT  48.048 14.197 49.464 14.867 ;
     RECT  31.392 12.563 31.416 16.019 ;
     RECT  45.072 12.757 45.912 16.019 ;
     RECT  34.8 14.819 35.112 16.501 ;
     RECT  48.048 14.867 48.072 17.461 ;
     RECT  49.344 14.867 49.464 17.461 ;
     RECT  51 2.151 51.312 17.653 ;
     RECT  48.048 17.461 49.464 18.661 ;
     RECT  50.736 17.653 51.312 18.803 ;
     RECT  47.904 18.661 49.464 18.851 ;
     RECT  48.912 18.851 49.464 20.003 ;
     RECT  47.904 18.851 47.928 21.541 ;
     RECT  49.344 20.003 49.464 21.541 ;
     RECT  47.904 21.541 49.464 21.589 ;
     RECT  23.04 14.197 24.312 21.637 ;
     RECT  47.856 21.589 49.464 21.731 ;
     RECT  0.144 20.389 0.168 22.307 ;
     RECT  45.6 16.019 45.912 22.741 ;
     RECT  26.352 21.013 26.376 23.173 ;
     RECT  44.976 22.741 45.912 23.221 ;
     RECT  40.2 13.139 40.512 23.269 ;
     RECT  51 18.803 51.312 23.365 ;
     RECT  44.976 23.221 46.008 23.603 ;
     RECT  44.976 23.603 45.912 23.651 ;
     RECT  23.04 21.637 25.224 23.893 ;
     RECT  26.352 23.173 27.336 23.893 ;
     RECT  50.688 23.365 51.312 23.987 ;
     RECT  47.904 21.731 49.464 24.083 ;
     RECT  34.56 16.501 35.112 24.227 ;
     RECT  40.2 23.269 41.016 24.323 ;
     RECT  47.184 25.045 47.208 25.285 ;
     RECT  45.6 23.651 45.912 25.477 ;
     RECT  48.384 24.083 49.464 25.621 ;
     RECT  48.384 25.621 49.848 26.149 ;
     RECT  45.6 25.477 46.152 26.243 ;
     RECT  47.184 25.285 47.304 26.581 ;
     RECT  48.336 26.149 49.848 26.581 ;
     RECT  47.184 26.581 49.848 26.867 ;
     RECT  47.28 26.867 49.848 26.915 ;
     RECT  51 23.987 51.312 27.109 ;
     RECT  50.88 27.109 52.2 27.251 ;
     RECT  45.6 26.243 45.912 27.301 ;
     RECT  43.872 27.301 43.896 27.445 ;
     RECT  45.264 27.301 45.912 27.445 ;
     RECT  47.568 26.915 49.848 27.877 ;
     RECT  50.88 27.251 51.312 27.877 ;
     RECT  53.808 27.733 53.832 27.923 ;
     RECT  43.872 27.445 45.912 28.259 ;
     RECT  44.16 28.259 45.912 28.307 ;
     RECT  44.448 28.307 45.912 28.547 ;
     RECT  47.568 27.877 51.312 28.547 ;
     RECT  47.568 28.547 49.944 28.595 ;
     RECT  45.504 28.547 45.912 28.933 ;
     RECT  45.504 28.933 46.536 29.267 ;
     RECT  45.6 29.267 46.536 29.365 ;
     RECT  47.568 28.595 49.56 29.365 ;
     RECT  23.04 23.893 27.336 30.467 ;
     RECT  45.6 29.365 49.56 30.565 ;
     RECT  36.576 30.181 36.6 30.709 ;
     RECT  45.312 30.565 49.56 30.709 ;
     RECT  44.88 30.709 49.56 30.949 ;
     RECT  44.88 30.949 49.8 31.043 ;
     RECT  44.88 31.043 45.912 31.187 ;
     RECT  34.8 24.227 35.112 31.237 ;
     RECT  36.096 30.709 36.6 31.237 ;
     RECT  34.8 31.237 36.6 31.667 ;
     RECT  47.328 31.043 49.8 31.715 ;
     RECT  36.096 31.667 36.6 31.763 ;
     RECT  51 28.547 51.312 31.765 ;
     RECT  36.432 31.763 36.6 31.955 ;
     RECT  45.312 31.187 45.912 32.437 ;
     RECT  47.328 31.715 49.56 32.531 ;
     RECT  36.72 32.053 36.744 32.915 ;
     RECT  24 30.467 27.336 33.011 ;
     RECT  47.328 32.531 49.464 33.013 ;
     RECT  44.976 32.437 46.152 33.107 ;
     RECT  47.232 33.013 49.464 33.251 ;
     RECT  44.976 33.107 46.056 33.539 ;
     RECT  26.16 33.011 27.336 33.587 ;
     RECT  48.336 33.251 49.464 33.589 ;
     RECT  50.592 31.765 51.312 33.589 ;
     RECT  24 33.011 24.408 33.827 ;
     RECT  48.336 33.589 51.312 33.875 ;
     RECT  50.688 33.875 51.312 34.259 ;
     RECT  44.976 33.539 45.912 34.499 ;
     RECT  47.232 33.251 47.352 34.549 ;
     RECT  48.336 33.875 49.464 34.549 ;
     RECT  26.16 33.587 26.184 34.643 ;
     RECT  47.232 34.549 49.464 34.835 ;
     RECT  47.232 34.835 48.984 34.883 ;
     RECT  27.312 33.587 27.336 34.931 ;
     RECT  48.96 34.883 48.984 34.931 ;
     RECT  47.232 34.883 47.832 34.933 ;
     RECT  45.504 34.499 45.912 35.027 ;
     RECT  45.6 35.027 45.912 35.461 ;
     RECT  47.04 34.933 47.832 35.461 ;
     RECT  45.6 35.461 47.832 35.941 ;
     RECT  45.6 35.941 47.976 36.035 ;
     RECT  47.616 36.035 47.976 36.277 ;
     RECT  47.616 36.277 48.408 36.515 ;
     RECT  47.808 36.515 48.408 36.757 ;
     RECT  47.808 36.757 48.552 36.997 ;
     RECT  47.808 36.997 49.416 37.667 ;
     RECT  47.808 37.667 48.408 37.955 ;
     RECT  45.6 36.035 46.344 38.723 ;
     RECT  47.808 37.955 47.88 38.819 ;
     RECT  49.392 37.667 49.416 38.819 ;
     RECT  47.856 38.819 47.88 39.395 ;
     RECT  49.536 39.877 49.56 40.499 ;
     RECT  2.4 2.151 2.712 41.049 ;
     RECT  7.8 2.151 8.112 41.049 ;
     RECT  13.2 2.151 13.512 41.049 ;
     RECT  18.6 11.315 18.912 41.049 ;
     RECT  24 33.827 24.312 41.049 ;
     RECT  29.4 8.579 29.712 41.049 ;
     RECT  34.8 31.667 35.112 41.049 ;
     RECT  40.2 24.323 40.512 41.049 ;
     RECT  45.6 38.723 45.912 41.049 ;
     RECT  51 34.259 51.312 41.049 ;
     RECT  2.4 41.049 2.52 41.063 ;
     RECT  7.8 41.049 7.92 41.063 ;
     RECT  13.2 41.049 13.32 41.063 ;
     RECT  18.6 41.049 18.72 41.063 ;
     RECT  24 41.049 24.12 41.063 ;
     RECT  29.4 41.049 29.52 41.063 ;
     RECT  34.8 41.049 34.92 41.063 ;
     RECT  40.2 41.049 40.32 41.063 ;
     RECT  45.6 41.049 45.72 41.063 ;
     RECT  51 41.049 51.12 41.063 ;
     RECT  19.08 1.763 20.208 1.811 ;
     RECT  38.184 1.763 39.696 1.811 ;
     RECT  19.032 1.811 20.208 2.291 ;
     RECT  32.904 2.195 34.032 3.443 ;
     RECT  19.032 2.291 20.304 2.963 ;
     RECT  21.864 2.915 23.04 3.443 ;
     RECT  24.936 2.915 25.968 4.019 ;
     RECT  17.448 2.963 18.48 3.107 ;
     RECT  18.912 2.963 20.304 3.443 ;
     RECT  26.28 3.011 27.696 3.443 ;
     RECT  17.448 3.107 18.6 3.491 ;
     RECT  26.232 3.443 27.696 4.261 ;
     RECT  32.904 3.443 34.176 4.067 ;
     RECT  24.504 4.019 25.968 4.595 ;
     RECT  26.232 4.261 27.312 5.075 ;
     RECT  26.184 5.075 27.312 6.611 ;
     RECT  29.712 5.171 30.864 5.747 ;
     RECT  23.04 5.555 23.328 7.045 ;
     RECT  29.712 5.747 31.008 6.947 ;
     RECT  35.112 6.899 36.144 7.475 ;
     RECT  22.104 7.045 23.328 8.003 ;
     RECT  35.112 7.475 35.208 8.869 ;
     RECT  22.104 8.003 23.616 9.155 ;
     RECT  22.632 11.365 24 12.227 ;
     RECT  48.072 13.813 49.44 14.197 ;
     RECT  48.072 14.867 49.344 17.461 ;
     RECT  49.464 17.653 50.736 18.803 ;
     RECT  47.928 18.851 48.912 20.003 ;
     RECT  47.928 20.003 49.344 21.541 ;
     RECT  25.224 21.637 26.352 23.893 ;
     RECT  49.464 23.365 50.688 23.987 ;
     RECT  45.912 23.603 46.008 25.045 ;
     RECT  47.904 24.083 48.384 25.045 ;
     RECT  45.912 25.045 47.184 25.477 ;
     RECT  47.208 25.045 48.384 25.285 ;
     RECT  47.304 25.285 48.384 26.149 ;
     RECT  46.152 25.477 47.184 26.243 ;
     RECT  49.848 25.621 51 27.109 ;
     RECT  47.304 26.149 48.336 26.581 ;
     RECT  45.912 26.243 47.184 26.867 ;
     RECT  45.912 26.867 47.28 26.915 ;
     RECT  49.848 27.109 50.88 27.877 ;
     RECT  43.896 27.301 45.264 27.445 ;
     RECT  49.944 28.547 51 28.595 ;
     RECT  49.56 28.595 51 30.949 ;
     RECT  46.536 28.933 47.568 29.365 ;
     RECT  45.504 29.267 45.6 30.565 ;
     RECT  35.112 30.181 36.576 30.709 ;
     RECT  35.112 30.709 36.096 31.237 ;
     RECT  49.8 30.949 51 31.715 ;
     RECT  45.912 31.043 47.328 32.437 ;
     RECT  44.976 31.187 45.312 32.437 ;
     RECT  35.112 31.667 36.096 31.763 ;
     RECT  49.56 31.715 51 31.765 ;
     RECT  35.112 31.763 36.432 31.955 ;
     RECT  49.56 31.765 50.592 32.531 ;
     RECT  46.152 32.437 47.328 33.013 ;
     RECT  49.464 32.531 50.592 33.589 ;
     RECT  46.152 33.013 47.232 33.107 ;
     RECT  46.056 33.107 47.232 33.539 ;
     RECT  47.352 33.251 48.336 34.549 ;
     RECT  45.912 33.539 47.232 34.933 ;
     RECT  26.184 33.587 27.312 34.643 ;
     RECT  49.464 33.875 50.688 34.259 ;
     RECT  47.832 34.883 48.96 34.931 ;
     RECT  47.832 34.931 48.408 35.941 ;
     RECT  45.912 34.933 47.04 35.461 ;
     RECT  47.976 35.941 48.408 36.277 ;
     RECT  46.344 36.035 47.616 36.515 ;
     RECT  46.344 36.515 47.808 38.723 ;
     RECT  48.408 37.667 49.392 37.955 ;
     RECT  47.88 37.955 49.392 38.819 ;
     RECT  49.56 39.877 51 40.499 ;
  END
END ot_qkh_head_stin_native
END LIBRARY
